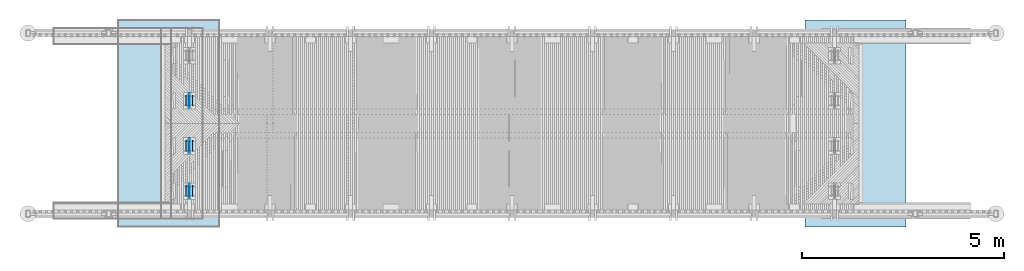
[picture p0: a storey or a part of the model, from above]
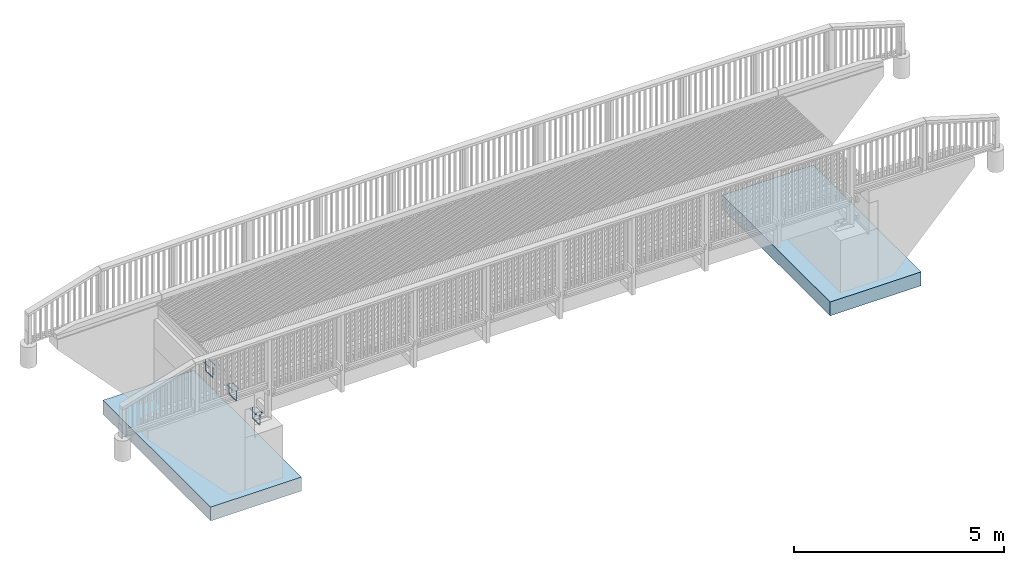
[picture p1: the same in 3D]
Properties of the parts of a building model (IFC2X3), part 1 of 2

# File
Description: ViewDefinition[CoordinationView_V2.0, QuantityTakeOffAddOnView], ExchangeRequirement[Structural, SurfaceGeometry]
File name: HKI_Puusilta_16_sks.ifc
Time: 2018-09-25T11:07:31
Author: SITO\jukka.karenniemi
Organization: Structural Designer
Written by: IFC Database Version:Work
Made in: Tekla Structures 2016i Service Pack 6, IFC Export Version: 4.0.0.0 Sep 13 2017

# IfcSite, Undefined
RefElevation: 0 mm

# IfcBuildingStorey, Undefined
In: Undefined
Elevation: 0 mm

# IfcBeam: 100*60 (32)
In: Undefined
Description: 100*60; Material: TIMBER/Timber_Undefined
Pset_BeamCommon - LoadBearing: yes; Reference: P/0(?)
Tekla Common - Phase: 600; Class: 1
Tekla Quantity - Weight: 1.2 kg; Volume: 0 m3; Gross footprint area: 0 m2; Area per tons: 108.1 m2; Net surface area: 0.1 m2; Height: 100 mm; Width: 55.3 mm; Length: 395 mm
BaseQuantities - Length: 395 mm
Name | Bottom elevation | Top elevation | OuterSurfaceArea (m2) | NetVolume (m3) | NetWeight (kg)
8 x BEAM | +2.484 | +2.584 | 0.12876 | 0.00198487 | 1.19092
8 x BEAM | +2.484 | +2.584 | 0.128766 | 0.00198513 | 1.19108
8 x BEAM | +2.005 | +2.105 | 0.12876 | 0.00198487 | 1.19092
8 x BEAM | +2.005 | +2.105 | 0.128766 | 0.00198513 | 1.19108

# IfcBeam: 150*100 (40)
In: Undefined
Description: 150*100; Material: TIMBER/Timber_Undefined
Tekla Common - Phase: 600; Class: 8004
Tekla Quantity - Volume: 0 m3; Gross footprint area: 0 m2; Height: 150 mm; Width: 100 mm
Pset_BeamCommon - LoadBearing: yes; Reference: TJP/0(?)
Name | Bottom elevation | Top elevation | Weight (kg) | Area per tons (m2) | Net surface area (m2) | Tekla Quantity, Length (mm) | BaseQuantities, Length (mm) | OuterSurfaceArea (m2) | NetVolume (m3) | NetWeight (kg)
4 x TÖRMÄYSJOHDE | +3.069 | +3.209 | 26 | 56.7 | 1.5 | 2885.3 | 2885.28 | 1.47264 | 0.0432791 | 25.9675
2 x TÖRMÄYSJOHDE | +3.145 | +3.249 | 3.6 | 63.9 | 0.2 | 400 | 399.996 | 0.229998 | 0.00599994 | 3.59997
2 x TÖRMÄYSJOHDE | +3.166 | +3.268 | 3.6 | 63.9 | 0.2 | 400 | 399.996 | 0.229998 | 0.00599994 | 3.59997
2 x TÖRMÄYSJOHDE | +3.160 | +3.261 | 3.6 | 63.9 | 0.2 | 400 | 399.996 | 0.229998 | 0.00599994 | 3.59997
2 x TÖRMÄYSJOHDE | +3.126 | +3.229 | 3.6 | 63.9 | 0.2 | 400 | 399.996 | 0.229998 | 0.00599994 | 3.59997
2 x TÖRMÄYSJOHDE | +3.146 | +3.249 | 2.3 | 68.9 | 0.2 | 250 | 250.001 | 0.155 | 0.00375001 | 2.25001
2 x TÖRMÄYSJOHDE | +3.113 | +3.216 | 2.3 | 68.9 | 0.2 | 250 | 250.001 | 0.155 | 0.00375001 | 2.25001
2 x TÖRMÄYSJOHDE | +3.126 | +3.229 | 2.3 | 68.9 | 0.2 | 250 | 250.001 | 0.155 | 0.00375001 | 2.25001
2 x TÖRMÄYSJOHDE | +3.137 | +3.239 | 2.3 | 68.9 | 0.2 | 250 | 250.001 | 0.155 | 0.00375001 | 2.25001
2 x TÖRMÄYSJOHDE | +3.154 | +3.255 | 2.3 | 68.9 | 0.2 | 250 | 250.001 | 0.155 | 0.00375001 | 2.25001
2 x TÖRMÄYSJOHDE | +3.160 | +3.261 | 2.3 | 68.9 | 0.2 | 250 | 250.001 | 0.155 | 0.00375001 | 2.25001
2 x TÖRMÄYSJOHDE | +3.165 | +3.265 | 2.3 | 68.9 | 0.2 | 250 | 250.001 | 0.155 | 0.00375001 | 2.25001
2 x TÖRMÄYSJOHDE | +3.168 | +3.268 | 2.3 | 68.9 | 0.2 | 250 | 250.001 | 0.155 | 0.00375001 | 2.25001
2 x TÖRMÄYSJOHDE | +3.167 | +3.268 | 2.3 | 68.9 | 0.2 | 250 | 250.001 | 0.155 | 0.00375001 | 2.25001
2 x TÖRMÄYSJOHDE | +3.164 | +3.265 | 2.3 | 68.9 | 0.2 | 250 | 250.001 | 0.155 | 0.00375001 | 2.25001
2 x TÖRMÄYSJOHDE | +3.154 | +3.256 | 2.3 | 68.9 | 0.2 | 250 | 250.001 | 0.155 | 0.00375001 | 2.25001
2 x TÖRMÄYSJOHDE | +3.137 | +3.240 | 2.3 | 68.9 | 0.2 | 250 | 250.001 | 0.155 | 0.00375001 | 2.25001
2 x TÖRMÄYSJOHDE | +3.113 | +3.217 | 2.3 | 68.9 | 0.2 | 250 | 250.001 | 0.155 | 0.00375001 | 2.25001
2 x TÖRMÄYSJOHDE | +3.108 | +3.212 | 2.3 | 68.9 | 0.2 | 250 | 250.001 | 0.155 | 0.00375001 | 2.25001

# IfcBeam: 150*150 (18)
In: Undefined
Description: 150*150; Material: TIMBER/Timber_Undefined
Pset_BeamCommon - LoadBearing: yes
Tekla Quantity - Height: 150 mm
Name | Reference | Bottom elevation | Top elevation | Phase | Class | Weight (kg) | Volume (m3) | Gross footprint area (m2) | Area per tons (m2) | Net surface area (m2) | Width (mm) | Tekla Quantity, Length (mm) | BaseQuantities, Length (mm) | OuterSurfaceArea (m2) | NetVolume (m3) | NetWeight (kg)
4 x TÖRMÄYSJOHDE | TJP/0(?) | +3.169 | +3.359 | 600 | 8004 | 36.4 | 0.1 | 0 | 46.9 | 1.7 | 150 | 2885.3 | 2885.28 | 1.70433 | 0.0606248 | 36.3749
6 x BEAM | P/0(?) | +2.584 | +2.734 | 600 | 1 | 12.2 | 0 | 0.1 | 48.1 | 0.6 | 150 | 900 | 900 | 0.585 | 0.02025 | 12.15
2 x BEAM | P/0(?) | +3.034 | +3.151 | 100 | 1 | 34.1 | 0.1 | 0 | 57.4 | 2 | 117.5 | 3930 | 3930 | 1.96088 | 0.0568959 | 34.1375
2 x BEAM | P/0(?) | +2.884 | +3.034 | 100 | 1 | 53.1 | 0.1 | 0.6 | 45.3 | 2.4 | 150 | 3930 | 3930 | 2.403 | 0.088425 | 53.055
2 x BEAM | P/0(?) | +2.734 | +2.884 | 100 | 1 | 53.1 | 0.1 | 0.6 | 45.3 | 2.4 | 150 | 3930 | 3930 | 2.403 | 0.088425 | 53.055
2 x TÖRMÄYSJOHDE | TJP/0(?) | +3.208 | +3.418 | 600 | 8004 | 228.7 | 0.3 | 0.1 | 44.6 | 10.1 | 150 | 16942.7 | 16942.7 | 10.2088 | 0.381144 | 228.686

# IfcBeam: 150*50 (676)
In: Undefined
Description: 150*50; Material: TIMBER/Timber_Undefined
Pset_BeamCommon - LoadBearing: yes; Reference: P/0(?)
Tekla Common - Phase: 400; Class: 1
Tekla Quantity - Volume: 0 m3; Gross footprint area: 0 m2; Height: 150 mm; Width: 50 mm
Name | Bottom elevation | Top elevation | Weight (kg) | Area per tons (m2) | Net surface area (m2) | Tekla Quantity, Length (mm) | BaseQuantities, Length (mm) | OuterSurfaceArea (m2) | NetVolume (m3) | NetWeight (kg)
2 x BEAM | +2.960 | +3.153 | 10.9 | 90.6 | 1 | 2510.6 | 2510.59 | 0.990985 | 0.0182401 | 10.944
2 x BEAM | +2.960 | +3.146 | 8.5 | 91 | 0.8 | 1928.4 | 1928.43 | 0.761386 | 0.013944 | 8.36639
2 x BEAM | +2.959 | +3.145 | 8.5 | 91 | 0.8 | 1928.4 | 1928.43 | 0.761386 | 0.013944 | 8.36639
2 x BEAM | +2.959 | +3.153 | 10.9 | 90.6 | 1 | 2510.6 | 2510.59 | 0.990985 | 0.0182401 | 10.944
2 x BEAM | +2.961 | +3.155 | 10.9 | 90.6 | 1 | 2510.6 | 2510.59 | 0.990985 | 0.0182401 | 10.944
2 x BEAM | +2.961 | +3.147 | 8.5 | 91 | 0.8 | 1928.4 | 1928.43 | 0.761386 | 0.013944 | 8.36639
2 x BEAM | +2.960 | +3.147 | 8.5 | 91 | 0.8 | 1928.4 | 1928.43 | 0.761386 | 0.013944 | 8.36639
2 x BEAM | +2.960 | +3.154 | 10.9 | 90.6 | 1 | 2510.6 | 2510.59 | 0.990985 | 0.0182401 | 10.944
2 x BEAM | +2.962 | +3.156 | 10.9 | 90.6 | 1 | 2510.6 | 2510.59 | 0.990985 | 0.0182401 | 10.944
2 x BEAM | +2.962 | +3.149 | 8.5 | 91 | 0.8 | 1928.4 | 1928.43 | 0.761386 | 0.013944 | 8.36639
2 x BEAM | +2.962 | +3.148 | 8.5 | 91 | 0.8 | 1928.4 | 1928.43 | 0.761386 | 0.013944 | 8.36639
2 x BEAM | +2.962 | +3.155 | 10.9 | 90.6 | 1 | 2510.6 | 2510.59 | 0.990985 | 0.0182401 | 10.944
2 x BEAM | +2.963 | +3.149 | 8.5 | 91 | 0.8 | 1928.4 | 1928.43 | 0.761386 | 0.013944 | 8.36639
2 x BEAM | +2.963 | +3.157 | 10.9 | 90.6 | 1 | 2510.6 | 2510.59 | 0.990985 | 0.0182401 | 10.944
2 x BEAM | +2.965 | +3.159 | 10.9 | 90.6 | 1 | 2510.6 | 2510.59 | 0.990985 | 0.0182401 | 10.944
2 x BEAM | +2.965 | +3.151 | 8.5 | 91 | 0.8 | 1928.4 | 1928.43 | 0.761386 | 0.013944 | 8.36639
2 x BEAM | +2.964 | +3.151 | 8.5 | 91 | 0.8 | 1928.4 | 1928.43 | 0.761386 | 0.013944 | 8.36639
2 x BEAM | +2.964 | +3.158 | 10.9 | 90.6 | 1 | 2510.6 | 2510.59 | 0.990985 | 0.0182401 | 10.944
2 x BEAM | +2.966 | +3.160 | 10.9 | 90.6 | 1 | 2510.6 | 2510.59 | 0.990985 | 0.0182401 | 10.944
2 x BEAM | +2.966 | +3.153 | 8.5 | 91 | 0.8 | 1928.4 | 1928.43 | 0.761386 | 0.013944 | 8.36639
2 x BEAM | +2.968 | +3.161 | 10.9 | 90.6 | 1 | 2510.6 | 2510.59 | 0.990985 | 0.0182401 | 10.944
2 x BEAM | +2.968 | +3.154 | 8.5 | 91 | 0.8 | 1928.4 | 1928.43 | 0.761386 | 0.013944 | 8.36639
2 x BEAM | +2.967 | +3.153 | 8.5 | 91 | 0.8 | 1928.4 | 1928.43 | 0.761386 | 0.013944 | 8.36639
2 x BEAM | +2.967 | +3.161 | 10.9 | 90.6 | 1 | 2510.6 | 2510.59 | 0.990985 | 0.0182401 | 10.944
2 x BEAM | +2.969 | +3.163 | 10.9 | 90.6 | 1 | 2510.6 | 2510.59 | 0.990985 | 0.0182401 | 10.944
2 x BEAM | +2.969 | +3.155 | 8.5 | 91 | 0.8 | 1928.4 | 1928.43 | 0.761386 | 0.013944 | 8.36639
2 x BEAM | +2.968 | +3.155 | 8.5 | 91 | 0.8 | 1928.4 | 1928.43 | 0.761386 | 0.013944 | 8.36639
2 x BEAM | +2.968 | +3.162 | 10.9 | 90.6 | 1 | 2510.6 | 2510.59 | 0.990985 | 0.0182401 | 10.944
2 x BEAM | +2.970 | +3.164 | 10.9 | 90.6 | 1 | 2510.6 | 2510.59 | 0.990985 | 0.0182401 | 10.944
2 x BEAM | +2.970 | +3.157 | 8.5 | 91 | 0.8 | 1928.4 | 1928.43 | 0.761386 | 0.013944 | 8.36639
2 x BEAM | +2.970 | +3.156 | 8.5 | 91 | 0.8 | 1928.4 | 1928.43 | 0.761386 | 0.013944 | 8.36639
2 x BEAM | +2.970 | +3.163 | 10.9 | 90.6 | 1 | 2510.6 | 2510.59 | 0.990985 | 0.0182401 | 10.944
2 x BEAM | +2.971 | +3.165 | 10.9 | 90.6 | 1 | 2510.6 | 2510.59 | 0.990985 | 0.0182401 | 10.944
2 x BEAM | +2.971 | +3.158 | 8.5 | 91 | 0.8 | 1928.4 | 1928.43 | 0.761386 | 0.013944 | 8.36639
2 x BEAM | +2.971 | +3.157 | 8.5 | 91 | 0.8 | 1928.4 | 1928.43 | 0.761386 | 0.013944 | 8.36639
2 x BEAM | +2.971 | +3.164 | 10.9 | 90.6 | 1 | 2510.6 | 2510.59 | 0.990985 | 0.0182401 | 10.944
2 x BEAM | +2.973 | +3.166 | 10.9 | 90.6 | 1 | 2510.6 | 2510.59 | 0.990985 | 0.0182401 | 10.944
2 x BEAM | +2.973 | +3.159 | 8.5 | 91 | 0.8 | 1928.4 | 1928.43 | 0.761386 | 0.013944 | 8.36639
2 x BEAM | +2.972 | +3.158 | 8.5 | 91 | 0.8 | 1928.4 | 1928.43 | 0.761386 | 0.013944 | 8.36639
2 x BEAM | +2.972 | +3.166 | 10.9 | 90.6 | 1 | 2510.6 | 2510.59 | 0.990985 | 0.0182401 | 10.944
2 x BEAM | +2.974 | +3.167 | 10.9 | 90.6 | 1 | 2510.6 | 2510.59 | 0.990985 | 0.0182401 | 10.944
2 x BEAM | +2.974 | +3.160 | 8.5 | 91 | 0.8 | 1928.4 | 1928.43 | 0.761386 | 0.013944 | 8.36639
2 x BEAM | +2.973 | +3.160 | 8.5 | 91 | 0.8 | 1928.4 | 1928.43 | 0.761386 | 0.013944 | 8.36639
2 x BEAM | +2.973 | +3.167 | 10.9 | 90.6 | 1 | 2510.6 | 2510.59 | 0.990985 | 0.0182401 | 10.944
2 x BEAM | +2.975 | +3.169 | 10.9 | 90.6 | 1 | 2510.6 | 2510.59 | 0.990985 | 0.0182401 | 10.944
4 x BEAM | +2.975 | +3.161 | 8.5 | 91 | 0.8 | 1928.4 | 1928.43 | 0.761386 | 0.013944 | 8.36639
2 x BEAM | +2.975 | +3.168 | 10.9 | 90.6 | 1 | 2510.6 | 2510.59 | 0.990985 | 0.0182401 | 10.944
2 x BEAM | +2.976 | +3.170 | 10.9 | 90.6 | 1 | 2510.6 | 2510.59 | 0.990985 | 0.0182401 | 10.944
2 x BEAM | +2.976 | +3.163 | 8.5 | 91 | 0.8 | 1928.4 | 1928.43 | 0.761386 | 0.013944 | 8.36639
2 x BEAM | +2.976 | +3.162 | 8.5 | 91 | 0.8 | 1928.4 | 1928.43 | 0.761386 | 0.013944 | 8.36639
2 x BEAM | +2.976 | +3.169 | 10.9 | 90.6 | 1 | 2510.6 | 2510.59 | 0.990985 | 0.0182401 | 10.944
2 x BEAM | +2.977 | +3.171 | 10.9 | 90.6 | 1 | 2510.6 | 2510.59 | 0.990985 | 0.0182401 | 10.944
2 x BEAM | +2.977 | +3.164 | 8.5 | 91 | 0.8 | 1928.4 | 1928.43 | 0.761386 | 0.013944 | 8.36639
2 x BEAM | +2.977 | +3.163 | 8.5 | 91 | 0.8 | 1928.4 | 1928.43 | 0.761386 | 0.013944 | 8.36639
2 x BEAM | +2.977 | +3.170 | 10.9 | 90.6 | 1 | 2510.6 | 2510.59 | 0.990985 | 0.0182401 | 10.944
2 x BEAM | +2.979 | +3.172 | 10.9 | 90.6 | 1 | 2510.6 | 2510.59 | 0.990985 | 0.0182401 | 10.944
2 x BEAM | +2.979 | +3.165 | 8.5 | 91 | 0.8 | 1928.4 | 1928.43 | 0.761386 | 0.013944 | 8.36639
2 x BEAM | +2.978 | +3.164 | 8.5 | 91 | 0.8 | 1928.4 | 1928.43 | 0.761386 | 0.013944 | 8.36639
2 x BEAM | +2.978 | +3.172 | 10.9 | 90.6 | 1 | 2510.6 | 2510.59 | 0.990985 | 0.0182401 | 10.944
2 x BEAM | +2.980 | +3.173 | 10.9 | 90.6 | 1 | 2510.6 | 2510.59 | 0.990985 | 0.0182401 | 10.944
2 x BEAM | +2.980 | +3.166 | 8.5 | 91 | 0.8 | 1928.4 | 1928.43 | 0.761386 | 0.013944 | 8.36639
2 x BEAM | +2.979 | +3.166 | 8.5 | 91 | 0.8 | 1928.4 | 1928.43 | 0.761386 | 0.013944 | 8.36639
2 x BEAM | +2.979 | +3.173 | 10.9 | 90.6 | 1 | 2510.6 | 2510.59 | 0.990985 | 0.0182401 | 10.944
2 x BEAM | +2.981 | +3.174 | 10.9 | 90.6 | 1 | 2510.6 | 2510.59 | 0.990985 | 0.0182401 | 10.944
2 x BEAM | +2.981 | +3.167 | 8.5 | 91 | 0.8 | 1928.4 | 1928.43 | 0.761386 | 0.013944 | 8.36639
2 x BEAM | +2.980 | +3.167 | 8.5 | 91 | 0.8 | 1928.4 | 1928.43 | 0.761386 | 0.013944 | 8.36639
2 x BEAM | +2.980 | +3.174 | 10.9 | 90.6 | 1 | 2510.6 | 2510.59 | 0.990985 | 0.0182401 | 10.944
2 x BEAM | +2.982 | +3.175 | 10.9 | 90.6 | 1 | 2510.6 | 2510.59 | 0.990985 | 0.0182401 | 10.944
2 x BEAM | +2.982 | +3.168 | 8.5 | 91 | 0.8 | 1928.4 | 1928.43 | 0.761386 | 0.013944 | 8.36639
2 x BEAM | +2.981 | +3.168 | 8.5 | 91 | 0.8 | 1928.4 | 1928.43 | 0.761386 | 0.013944 | 8.36639
2 x BEAM | +2.981 | +3.175 | 10.9 | 90.6 | 1 | 2510.6 | 2510.59 | 0.990985 | 0.0182401 | 10.944
2 x BEAM | +2.983 | +3.177 | 10.9 | 90.6 | 1 | 2510.6 | 2510.59 | 0.990985 | 0.0182401 | 10.944
4 x BEAM | +2.983 | +3.169 | 8.5 | 91 | 0.8 | 1928.4 | 1928.43 | 0.761386 | 0.013944 | 8.36639
2 x BEAM | +2.983 | +3.176 | 10.9 | 90.6 | 1 | 2510.6 | 2510.59 | 0.990985 | 0.0182401 | 10.944
2 x BEAM | +2.984 | +3.178 | 10.9 | 90.6 | 1 | 2510.6 | 2510.59 | 0.990985 | 0.0182401 | 10.944
4 x BEAM | +2.984 | +3.170 | 8.5 | 91 | 0.8 | 1928.4 | 1928.43 | 0.761386 | 0.013944 | 8.36639
2 x BEAM | +2.984 | +3.177 | 10.9 | 90.6 | 1 | 2510.6 | 2510.59 | 0.990985 | 0.0182401 | 10.944
2 x BEAM | +2.985 | +3.179 | 10.9 | 90.6 | 1 | 2510.6 | 2510.59 | 0.990985 | 0.0182401 | 10.944
4 x BEAM | +2.985 | +3.171 | 8.5 | 91 | 0.8 | 1928.4 | 1928.43 | 0.761386 | 0.013944 | 8.36639
2 x BEAM | +2.985 | +3.178 | 10.9 | 90.6 | 1 | 2510.6 | 2510.59 | 0.990985 | 0.0182401 | 10.944
2 x BEAM | +2.986 | +3.180 | 10.9 | 90.6 | 1 | 2510.6 | 2510.59 | 0.990985 | 0.0182401 | 10.944
3 x BEAM | +2.986 | +3.172 | 8.5 | 91 | 0.8 | 1928.4 | 1928.43 | 0.761386 | 0.013944 | 8.36639
2 x BEAM | +2.986 | +3.179 | 10.9 | 90.6 | 1 | 2510.6 | 2510.59 | 0.990985 | 0.0182401 | 10.944
2 x BEAM | +2.987 | +3.173 | 8.5 | 91 | 0.8 | 1928.4 | 1928.43 | 0.761386 | 0.013944 | 8.36639
2 x BEAM | +2.987 | +3.180 | 10.9 | 90.6 | 1 | 2510.6 | 2510.59 | 0.990985 | 0.0182401 | 10.944
2 x BEAM | +2.988 | +3.182 | 10.9 | 90.6 | 1 | 2510.6 | 2510.59 | 0.990985 | 0.0182401 | 10.944
2 x BEAM | +2.988 | +3.175 | 8.5 | 91 | 0.8 | 1928.4 | 1928.43 | 0.761386 | 0.013944 | 8.36639
2 x BEAM | +2.988 | +3.174 | 8.5 | 91 | 0.8 | 1928.4 | 1928.43 | 0.761386 | 0.013944 | 8.36639
2 x BEAM | +2.988 | +3.181 | 10.9 | 90.6 | 1 | 2510.6 | 2510.59 | 0.990985 | 0.0182401 | 10.944
2 x BEAM | +2.989 | +3.183 | 10.9 | 90.6 | 1 | 2510.6 | 2510.59 | 0.990985 | 0.0182401 | 10.944
2 x BEAM | +2.989 | +3.175 | 8.5 | 91 | 0.8 | 1928.4 | 1928.43 | 0.761386 | 0.013944 | 8.36639
2 x BEAM | +2.990 | +3.184 | 10.9 | 90.6 | 1 | 2510.6 | 2510.59 | 0.990985 | 0.0182401 | 10.944
4 x BEAM | +2.990 | +3.176 | 8.5 | 91 | 0.8 | 1928.4 | 1928.43 | 0.761386 | 0.013944 | 8.36639
2 x BEAM | +2.990 | +3.183 | 10.9 | 90.6 | 1 | 2510.6 | 2510.59 | 0.990985 | 0.0182401 | 10.944
2 x BEAM | +2.991 | +3.185 | 10.9 | 90.6 | 1 | 2510.6 | 2510.59 | 0.990985 | 0.0182401 | 10.944
4 x BEAM | +2.991 | +3.177 | 8.5 | 91 | 0.8 | 1928.4 | 1928.43 | 0.761386 | 0.013944 | 8.36639
2 x BEAM | +2.991 | +3.184 | 10.9 | 90.6 | 1 | 2510.6 | 2510.59 | 0.990985 | 0.0182401 | 10.944
2 x BEAM | +2.992 | +3.186 | 10.9 | 90.6 | 1 | 2510.6 | 2510.59 | 0.990985 | 0.0182401 | 10.944
4 x BEAM | +2.992 | +3.178 | 8.5 | 91 | 0.8 | 1928.4 | 1928.43 | 0.761386 | 0.013944 | 8.36639
2 x BEAM | +2.992 | +3.185 | 10.9 | 90.6 | 1 | 2510.6 | 2510.59 | 0.990985 | 0.0182401 | 10.944
4 x BEAM | +2.993 | +3.186 | 10.9 | 90.6 | 1 | 2510.6 | 2510.59 | 0.990985 | 0.0182401 | 10.944
4 x BEAM | +2.993 | +3.179 | 8.5 | 91 | 0.8 | 1928.4 | 1928.43 | 0.761386 | 0.013944 | 8.36639
2 x BEAM | +2.994 | +3.187 | 10.9 | 90.6 | 1 | 2510.6 | 2510.59 | 0.990985 | 0.0182401 | 10.944
2 x BEAM | +2.994 | +3.180 | 8.5 | 91 | 0.8 | 1928.4 | 1928.43 | 0.761386 | 0.013944 | 8.36639
2 x BEAM | +2.993 | +3.180 | 8.5 | 91 | 0.8 | 1928.4 | 1928.43 | 0.761386 | 0.013944 | 8.36639
2 x BEAM | +2.993 | +3.187 | 10.9 | 90.6 | 1 | 2510.6 | 2510.59 | 0.990985 | 0.0182401 | 10.944
2 x BEAM | +2.995 | +3.188 | 10.9 | 90.6 | 1 | 2510.6 | 2510.59 | 0.990985 | 0.0182401 | 10.944
4 x BEAM | +2.995 | +3.181 | 8.5 | 91 | 0.8 | 1928.4 | 1928.43 | 0.761386 | 0.013944 | 8.36639
2 x BEAM | +2.994 | +3.181 | 8.5 | 91 | 0.8 | 1928.4 | 1928.43 | 0.761386 | 0.013944 | 8.36639
2 x BEAM | +2.994 | +3.188 | 10.9 | 90.6 | 1 | 2510.6 | 2510.59 | 0.990985 | 0.0182401 | 10.944
2 x BEAM | +2.996 | +3.189 | 10.9 | 90.6 | 1 | 2510.6 | 2510.59 | 0.990985 | 0.0182401 | 10.944
4 x BEAM | +2.996 | +3.182 | 8.5 | 91 | 0.8 | 1928.4 | 1928.43 | 0.761386 | 0.013944 | 8.36639
2 x BEAM | +2.995 | +3.189 | 10.9 | 90.6 | 1 | 2510.6 | 2510.59 | 0.990985 | 0.0182401 | 10.944
4 x BEAM | +2.997 | +3.190 | 10.9 | 90.6 | 1 | 2510.6 | 2510.59 | 0.990985 | 0.0182401 | 10.944
4 x BEAM | +2.997 | +3.183 | 8.5 | 91 | 0.8 | 1928.4 | 1928.43 | 0.761386 | 0.013944 | 8.36639
2 x BEAM | +2.996 | +3.190 | 10.9 | 90.6 | 1 | 2510.6 | 2510.59 | 0.990985 | 0.0182401 | 10.944
2 x BEAM | +2.997 | +3.191 | 10.9 | 90.6 | 1 | 2510.6 | 2510.59 | 0.990985 | 0.0182401 | 10.944
2 x BEAM | +2.997 | +3.184 | 8.5 | 91 | 0.8 | 1928.4 | 1928.43 | 0.761386 | 0.013944 | 8.36639
2 x BEAM | +2.998 | +3.192 | 10.9 | 90.6 | 1 | 2510.6 | 2510.59 | 0.990985 | 0.0182401 | 10.944
4 x BEAM | +2.998 | +3.184 | 8.5 | 91 | 0.8 | 1928.4 | 1928.43 | 0.761386 | 0.013944 | 8.36639
2 x BEAM | +2.998 | +3.191 | 10.9 | 90.6 | 1 | 2510.6 | 2510.59 | 0.990985 | 0.0182401 | 10.944
4 x BEAM | +2.999 | +3.192 | 10.9 | 90.6 | 1 | 2510.6 | 2510.59 | 0.990985 | 0.0182401 | 10.944
4 x BEAM | +2.999 | +3.185 | 8.5 | 91 | 0.8 | 1928.4 | 1928.43 | 0.761386 | 0.013944 | 8.36639
2 x BEAM | +3.000 | +3.193 | 10.9 | 90.6 | 1 | 2510.6 | 2510.59 | 0.990985 | 0.0182401 | 10.944
4 x BEAM | +3.000 | +3.186 | 8.5 | 91 | 0.8 | 1928.4 | 1928.43 | 0.761386 | 0.013944 | 8.36639
2 x BEAM | +2.999 | +3.186 | 8.5 | 91 | 0.8 | 1928.4 | 1928.43 | 0.761386 | 0.013944 | 8.36639
2 x BEAM | +2.999 | +3.193 | 10.9 | 90.6 | 1 | 2510.6 | 2510.59 | 0.990985 | 0.0182401 | 10.944
4 x BEAM | +3.001 | +3.194 | 10.9 | 90.6 | 1 | 2510.6 | 2510.59 | 0.990985 | 0.0182401 | 10.944
6 x BEAM | +3.001 | +3.187 | 8.5 | 91 | 0.8 | 1928.4 | 1928.43 | 0.761386 | 0.013944 | 8.36639
2 x BEAM | +3.000 | +3.194 | 10.9 | 90.6 | 1 | 2510.6 | 2510.59 | 0.990985 | 0.0182401 | 10.944
2 x BEAM | +3.001 | +3.195 | 10.9 | 90.6 | 1 | 2510.6 | 2510.59 | 0.990985 | 0.0182401 | 10.944
4 x BEAM | +3.002 | +3.195 | 10.9 | 90.6 | 1 | 2510.6 | 2510.59 | 0.990985 | 0.0182401 | 10.944
4 x BEAM | +3.002 | +3.188 | 8.5 | 91 | 0.8 | 1928.4 | 1928.43 | 0.761386 | 0.013944 | 8.36639
4 x BEAM | +3.003 | +3.196 | 10.9 | 90.6 | 1 | 2510.6 | 2510.59 | 0.990985 | 0.0182401 | 10.944
4 x BEAM | +3.003 | +3.189 | 8.5 | 91 | 0.8 | 1928.4 | 1928.43 | 0.761386 | 0.013944 | 8.36639
2 x BEAM | +3.002 | +3.189 | 8.5 | 91 | 0.8 | 1928.4 | 1928.43 | 0.761386 | 0.013944 | 8.36639
2 x BEAM | +3.002 | +3.196 | 10.9 | 90.6 | 1 | 2510.6 | 2510.59 | 0.990985 | 0.0182401 | 10.944
4 x BEAM | +3.004 | +3.197 | 10.9 | 90.6 | 1 | 2510.6 | 2510.59 | 0.990985 | 0.0182401 | 10.944
4 x BEAM | +3.004 | +3.190 | 8.5 | 91 | 0.8 | 1928.4 | 1928.43 | 0.761386 | 0.013944 | 8.36639
4 x BEAM | +3.005 | +3.198 | 10.9 | 90.6 | 1 | 2510.6 | 2510.59 | 0.990985 | 0.0182401 | 10.944
4 x BEAM | +3.005 | +3.191 | 8.5 | 91 | 0.8 | 1928.4 | 1928.43 | 0.761386 | 0.013944 | 8.36639
6 x BEAM | +3.006 | +3.199 | 10.9 | 90.6 | 1 | 2510.6 | 2510.59 | 0.990985 | 0.0182401 | 10.944
6 x BEAM | +3.006 | +3.192 | 8.5 | 91 | 0.8 | 1928.4 | 1928.43 | 0.761386 | 0.013944 | 8.36639
4 x BEAM | +3.007 | +3.200 | 10.9 | 90.6 | 1 | 2510.6 | 2510.59 | 0.990985 | 0.0182401 | 10.944
6 x BEAM | +3.007 | +3.193 | 8.5 | 91 | 0.8 | 1928.4 | 1928.43 | 0.761386 | 0.013944 | 8.36639
2 x BEAM | +3.006 | +3.193 | 8.5 | 91 | 0.8 | 1928.4 | 1928.43 | 0.761386 | 0.013944 | 8.36639
2 x BEAM | +3.006 | +3.200 | 10.9 | 90.6 | 1 | 2510.6 | 2510.59 | 0.990985 | 0.0182401 | 10.944
2 x BEAM | +3.007 | +3.201 | 10.9 | 90.6 | 1 | 2510.6 | 2510.59 | 0.990985 | 0.0182401 | 10.944
4 x BEAM | +3.008 | +3.201 | 10.9 | 90.6 | 1 | 2510.6 | 2510.59 | 0.990985 | 0.0182401 | 10.944
6 x BEAM | +3.008 | +3.194 | 8.5 | 91 | 0.8 | 1928.4 | 1928.43 | 0.761386 | 0.013944 | 8.36639
6 x BEAM | +3.009 | +3.202 | 10.9 | 90.6 | 1 | 2510.6 | 2510.59 | 0.990985 | 0.0182401 | 10.944
8 x BEAM | +3.009 | +3.195 | 8.5 | 91 | 0.8 | 1928.4 | 1928.43 | 0.761386 | 0.013944 | 8.36639
2 x BEAM | +3.008 | +3.202 | 10.9 | 90.6 | 1 | 2510.6 | 2510.59 | 0.990985 | 0.0182401 | 10.944
6 x BEAM | +3.010 | +3.203 | 10.9 | 90.6 | 1 | 2510.6 | 2510.59 | 0.990985 | 0.0182401 | 10.944
8 x BEAM | +3.010 | +3.196 | 8.5 | 91 | 0.8 | 1928.4 | 1928.43 | 0.761386 | 0.013944 | 8.36639
2 x BEAM | +3.009 | +3.203 | 10.9 | 90.6 | 1 | 2510.6 | 2510.59 | 0.990985 | 0.0182401 | 10.944
6 x BEAM | +3.011 | +3.204 | 10.9 | 90.6 | 1 | 2510.6 | 2510.59 | 0.990985 | 0.0182401 | 10.944
8 x BEAM | +3.011 | +3.197 | 8.5 | 91 | 0.8 | 1928.4 | 1928.43 | 0.761386 | 0.013944 | 8.36639
2 x BEAM | +3.010 | +3.204 | 10.9 | 90.6 | 1 | 2510.6 | 2510.59 | 0.990985 | 0.0182401 | 10.944
6 x BEAM | +3.012 | +3.205 | 10.9 | 90.6 | 1 | 2510.6 | 2510.59 | 0.990985 | 0.0182401 | 10.944
8 x BEAM | +3.012 | +3.198 | 8.5 | 91 | 0.8 | 1928.4 | 1928.43 | 0.761386 | 0.013944 | 8.36639
2 x BEAM | +3.011 | +3.205 | 10.9 | 90.6 | 1 | 2510.6 | 2510.59 | 0.990985 | 0.0182401 | 10.944
8 x BEAM | +3.013 | +3.206 | 10.9 | 90.6 | 1 | 2510.6 | 2510.59 | 0.990985 | 0.0182401 | 10.944
10 x BEAM | +3.013 | +3.199 | 8.5 | 91 | 0.8 | 1928.4 | 1928.43 | 0.761386 | 0.013944 | 8.36639
2 x BEAM | +3.012 | +3.206 | 10.9 | 90.6 | 1 | 2510.6 | 2510.59 | 0.990985 | 0.0182401 | 10.944
2 x BEAM | +3.013 | +3.207 | 10.9 | 90.6 | 1 | 2510.6 | 2510.59 | 0.990985 | 0.0182401 | 10.944
10 x BEAM | +3.014 | +3.207 | 10.9 | 90.6 | 1 | 2510.6 | 2510.59 | 0.990985 | 0.0182401 | 10.944
10 x BEAM | +3.014 | +3.200 | 8.5 | 91 | 0.8 | 1928.4 | 1928.43 | 0.761386 | 0.013944 | 8.36639
8 x BEAM | +3.015 | +3.208 | 10.9 | 90.6 | 1 | 2510.6 | 2510.59 | 0.990985 | 0.0182401 | 10.944
10 x BEAM | +3.015 | +3.201 | 8.5 | 91 | 0.8 | 1928.4 | 1928.43 | 0.761386 | 0.013944 | 8.36639
2 x BEAM | +3.015 | +3.209 | 10.9 | 90.6 | 1 | 2510.6 | 2510.59 | 0.990985 | 0.0182401 | 10.944
12 x BEAM | +3.016 | +3.209 | 10.9 | 90.6 | 1 | 2510.6 | 2510.59 | 0.990985 | 0.0182401 | 10.944
14 x BEAM | +3.016 | +3.202 | 8.5 | 91 | 0.8 | 1928.4 | 1928.43 | 0.761386 | 0.013944 | 8.36639
20 x BEAM | +3.017 | +3.210 | 10.9 | 90.6 | 1 | 2510.6 | 2510.59 | 0.990985 | 0.0182401 | 10.944
2 x BEAM | +3.017 | +3.202 | 8.5 | 91 | 0.8 | 1928.4 | 1928.43 | 0.761386 | 0.013944 | 8.36639
2 x BEAM | +3.016 | +3.210 | 10.9 | 90.6 | 1 | 2510.6 | 2510.59 | 0.990985 | 0.0182401 | 10.944
20 x BEAM | +3.017 | +3.203 | 8.5 | 91 | 0.8 | 1928.4 | 1928.43 | 0.761386 | 0.013944 | 8.36639
2 x BEAM | +3.017 | +3.211 | 10.9 | 90.6 | 1 | 2510.6 | 2510.59 | 0.990985 | 0.0182401 | 10.944
32 x BEAM | +3.018 | +3.211 | 10.9 | 90.6 | 1 | 2510.6 | 2510.59 | 0.990985 | 0.0182401 | 10.944
4 x BEAM | +3.018 | +3.203 | 8.5 | 91 | 0.8 | 1928.4 | 1928.43 | 0.761386 | 0.013944 | 8.36639
28 x BEAM | +3.018 | +3.204 | 8.5 | 91 | 0.8 | 1928.4 | 1928.43 | 0.761386 | 0.013944 | 8.36639
2 x BEAM | +2.959 | +3.157 | 12.2 | 90.4 | 1.1 | 2768.6 | 2768.59 | 1.09418 | 0.0201751 | 12.105
2 x BEAM | +2.959 | +3.150 | 9.5 | 90.6 | 0.8 | 2186.4 | 2186.43 | 0.864586 | 0.015879 | 9.52739
2 x BEAM | +2.961 | +3.152 | 9.5 | 90.6 | 0.8 | 2186.4 | 2186.43 | 0.864586 | 0.015879 | 9.52739
2 x BEAM | +2.961 | +3.159 | 12.2 | 90.4 | 1.1 | 2768.6 | 2768.59 | 1.09418 | 0.0201751 | 12.105
2 x BEAM | +2.982 | +3.181 | 12.2 | 90.4 | 1.1 | 2768.6 | 2768.59 | 1.09418 | 0.0201751 | 12.105
2 x BEAM | +2.982 | +3.174 | 9.5 | 90.6 | 0.8 | 2186.4 | 2186.43 | 0.864586 | 0.015879 | 9.52739
2 x BEAM | +2.984 | +3.175 | 9.5 | 90.6 | 0.8 | 2186.4 | 2186.43 | 0.864586 | 0.015879 | 9.52739
2 x BEAM | +2.984 | +3.182 | 12.2 | 90.4 | 1.1 | 2768.6 | 2768.59 | 1.09418 | 0.0201751 | 12.105
2 x BEAM | +2.999 | +3.198 | 12.2 | 90.4 | 1.1 | 2768.6 | 2768.59 | 1.09418 | 0.0201751 | 12.105
2 x BEAM | +2.999 | +3.190 | 9.5 | 90.6 | 0.8 | 2186.4 | 2186.43 | 0.864586 | 0.015879 | 9.52739
2 x BEAM | +3.000 | +3.191 | 9.5 | 90.6 | 0.8 | 2186.4 | 2186.43 | 0.864586 | 0.015879 | 9.52739
BEAM | +3.000 | +3.198 | 12.2 | 90.4 | 1.1 | 2768.6 | 2768.59 | 1.09418 | 0.0201751 | 12.105
2 x BEAM | +3.009 | +3.208 | 12.2 | 90.4 | 1.1 | 2768.6 | 2768.59 | 1.09418 | 0.0201751 | 12.105
2 x BEAM | +3.009 | +3.200 | 9.5 | 90.6 | 0.8 | 2186.4 | 2186.43 | 0.864586 | 0.015879 | 9.52739
2 x BEAM | +3.010 | +3.201 | 9.5 | 90.6 | 0.8 | 2186.4 | 2186.43 | 0.864586 | 0.015879 | 9.52739
2 x BEAM | +3.010 | +3.208 | 12.2 | 90.4 | 1.1 | 2768.6 | 2768.59 | 1.09418 | 0.0201751 | 12.105
2 x BEAM | +3.013 | +3.211 | 12.2 | 90.4 | 1.1 | 2768.6 | 2768.59 | 1.09418 | 0.0201751 | 12.105
2 x BEAM | +3.013 | +3.204 | 9.5 | 90.6 | 0.8 | 2186.4 | 2186.43 | 0.864586 | 0.015879 | 9.52739
BEAM | +3.000 | +3.199 | 12.2 | 90.4 | 1.1 | 2768.6 | 2768.59 | 1.09418 | 0.0201751 | 12.105
BEAM | +2.986 | +3.173 | 8.5 | 91 | 0.8 | 1928.4 | 1928.43 | 0.761386 | 0.013944 | 8.36639

# IfcBeam: 1524*1035 (2)
In: Undefined
Description: 1524*1035; Material: CONCRETE/Concrete_Undefined
Pset_BeamCommon - LoadBearing: yes; Reference: Concrete_LP-1001/0(?)
Tekla Common - Bottom elevation: +0.400; Top elevation: +1.924; Phase: 100; Class: 1007
Tekla Quantity - Weight: 17812.3 kg; Volume: 7.4 m3; Gross footprint area: 1.2 m2; Area per tons: 1.6 m2; Net surface area: 27.8 m2; Height: 1524 mm; Width: 1035 mm; Length: 4730 mm
BaseQuantities - Length: 4730 mm; OuterSurfaceArea: 27.7914 m2; NetVolume: 7.42179 m3; NetWeight: 17812.3 kg

# IfcBeam: 180*100 (18)
In: Undefined
Description: 180*100; Material: TIMBER/Timber_Undefined
Tekla Common - Phase: 600; Class: 8013
Tekla Quantity - Weight: 4 kg; Volume: 0 m3; Gross footprint area: 0 m2; Area per tons: 61 m2; Net surface area: 0.2 m2; Height: 180 mm; Width: 100 mm
Pset_BeamCommon - LoadBearing: yes; Reference: KPP/0(?)
Name | Bottom elevation | Top elevation | Tekla Quantity, Length (mm) | BaseQuantities, Length (mm) | OuterSurfaceArea (m2) | NetVolume (m3) | NetWeight (kg)
2 x KAIDEPYLVÄS | +2.295 | +2.475 | 362.5 | 362.49 | 0.238994 | 0.00652482 | 3.91489
2 x KAIDEPYLVÄS | +2.295 | +2.475 | 363.7 | 363.74 | 0.239694 | 0.00654732 | 3.92839
2 x KAIDEPYLVÄS | +2.318 | +2.498 | 362.5 | 362.49 | 0.238994 | 0.00652482 | 3.91489
2 x KAIDEPYLVÄS | +2.318 | +2.498 | 363.7 | 363.74 | 0.239694 | 0.00654732 | 3.92839
2 x KAIDEPYLVÄS | +2.335 | +2.515 | 362.5 | 362.49 | 0.238994 | 0.00652482 | 3.91489
2 x KAIDEPYLVÄS | +2.335 | +2.515 | 363.7 | 363.74 | 0.239694 | 0.00654732 | 3.92839
2 x KAIDEPYLVÄS | +2.345 | +2.525 | 362.5 | 362.49 | 0.238994 | 0.00652482 | 3.91489
2 x KAIDEPYLVÄS | +2.345 | +2.525 | 363.7 | 363.74 | 0.239694 | 0.00654732 | 3.92839
KAIDEPYLVÄS | +2.348 | +2.528 | 362.5 | 362.49 | 0.238994 | 0.00652482 | 3.91489
KAIDEPYLVÄS | +2.348 | +2.528 | 363.7 | 363.74 | 0.239694 | 0.00654732 | 3.92839

# IfcBeam: 180*70 (6)
In: Undefined
Description: 180*70; Material: TIMBER/Timber_Undefined
Tekla Common - Phase: 600; Class: 8006
Tekla Quantity - Height: 180 mm; Width: 70 mm
Pset_BeamCommon - LoadBearing: yes; Reference: YJP/0(?)
Name | Bottom elevation | Top elevation | Weight (kg) | Volume (m3) | Gross footprint area (m2) | Area per tons (m2) | Net surface area (m2) | Tekla Quantity, Length (mm) | BaseQuantities, Length (mm) | OuterSurfaceArea (m2) | NetVolume (m3) | NetWeight (kg)
4 x YLÄJOHDE | +3.881 | +4.551 | 15.8 | 0 | 0 | 67.8 | 1.1 | 2108 | 2108.03 | 1.06987 | 0.026298 | 15.7788
2 x YLÄJOHDE | +4.480 | +4.633 | 151.8 | 0.3 | 0.1 | 66.3 | 10.1 | 20082.1 | 20082.1 | 10.0657 | 0.25302 | 151.812

# IfcBeam: 195*40 (4)
In: Undefined
Description: 195*40; Material: TIMBER/Timber_Undefined
Pset_BeamCommon - LoadBearing: yes; Reference: P/0(?)
Tekla Common - Bottom elevation: +3.081; Top elevation: +3.149; Phase: 600; Class: 1
Tekla Quantity - Weight: 8.5 kg; Volume: 0 m3; Gross footprint area: 0 m2; Area per tons: 102.3 m2; Net surface area: 0.8 m2; Height: 195 mm; Width: 40 mm; Length: 1820.2 mm
BaseQuantities - Length: 1820.22 mm; OuterSurfaceArea: 0.871104 m2; NetVolume: 0.0141977 m3; NetWeight: 8.51864 kg

# IfcBeam: 195*45 (20)
In: Undefined
Description: 195*45; Material: TIMBER/Timber_Undefined
Pset_BeamCommon - LoadBearing: yes; Reference: P/0(?)
Tekla Common - Phase: 600; Class: 1
Tekla Quantity - Volume: 0 m3; Gross footprint area: 0 m2; Area per tons: 92.9 m2; Net surface area: 0.8 m2; Height: 195 mm; Width: 45 mm
Name | Bottom elevation | Top elevation | Weight (kg) | Tekla Quantity, Length (mm) | BaseQuantities, Length (mm) | OuterSurfaceArea (m2) | NetVolume (m3) | NetWeight (kg)
4 x BEAM | +2.835 | +2.903 | 9.9 | 1880.2 | 1880.22 | 0.920056 | 0.0164989 | 9.89937
4 x BEAM | +2.859 | +2.920 | 9.9 | 1880.2 | 1880.22 | 0.920056 | 0.0164989 | 9.89937
2 x BEAM | +2.875 | +2.930 | 9.9 | 1880.2 | 1880.22 | 0.920056 | 0.0164989 | 9.89937
4 x BEAM | +2.885 | +2.933 | 9.9 | 1880.2 | 1880.22 | 0.920056 | 0.0164989 | 9.89937
2 x BEAM | +2.872 | +2.927 | 9.9 | 1880.2 | 1880.22 | 0.920056 | 0.0164989 | 9.89937
4 x BEAM | +3.107 | +3.180 | 9.7 | 1850.2 | 1850.22 | 0.905656 | 0.0162357 | 9.74142

# IfcBeam: 2800*400 (4)
In: Undefined
Description: 2800*400; Material: CONCRETE/Concrete_Undefined
Tekla Common - Bottom elevation: +0.400; Top elevation: +3.113; Phase: 100; Class: 1013
Tekla Quantity - Weight: 4355.7 kg; Volume: 1.8 m3; Gross footprint area: 0 m2; Area per tons: 3 m2; Net surface area: 13 m2; Height: 2708.8 mm; Width: 400 mm; Length: 2919.2 mm
Pset_BeamCommon - LoadBearing: yes; Reference: Concrete_LP-1001/0(?)
BaseQuantities - Length: 2919.22 mm; OuterSurfaceArea: 13.0098 m2; NetVolume: 1.81489 m3; NetWeight: 4355.74 kg

# IfcBeam: 50*50 (546)
In: Undefined
Description: 50*50; Material: TIMBER/Timber_Undefined
Pset_BeamCommon - LoadBearing: yes; Reference: P/0(?)
Tekla Common - Phase: 400; Class: 1
Tekla Quantity - Volume: 0 m3; Gross footprint area: 0 m2; Width: 50 mm
Name | Bottom elevation | Top elevation | Weight (kg) | Area per tons (m2) | Net surface area (m2) | Height (mm) | Tekla Quantity, Length (mm) | BaseQuantities, Length (mm) | OuterSurfaceArea (m2) | NetVolume (m3) | NetWeight (kg)
2 x BEAM | +3.109 | +3.160 | 0 | 406.5 | 0 | 24.3 | 48.6 | 48.6074 | 0.00683744 | 0.0000280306 | 0.0168184
2 x BEAM | +3.110 | +3.161 | 0.1 | 181.8 | 0 | 50 | 148.6 | 148.584 | 0.0265387 | 0.000243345 | 0.146007
BEAM | +3.149 | +3.200 | 0 | 485.4 | 0 | 19.3 | 39.7 | 39.6953 | 0.00537729 | 0.0000184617 | 0.011077
BEAM | +3.149 | +3.200 | 0 | 485.8 | 0 | 19.3 | 39.7 | 39.6884 | 0.00537407 | 0.0000184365 | 0.0110619
BEAM | +3.147 | +3.201 | 0.1 | 186.6 | 0 | 50 | 139.7 | 139.743 | 0.0247705 | 0.000221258 | 0.132755
BEAM | +3.147 | +3.201 | 0.1 | 186.6 | 0 | 50 | 139.7 | 139.736 | 0.0247626 | 0.000221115 | 0.132669
BEAM | +3.146 | +3.202 | 0.3 | 158.3 | 0 | 50 | 239.8 | 239.789 | 0.0447806 | 0.000471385 | 0.282831
BEAM | +3.146 | +3.202 | 0.3 | 158.3 | 0 | 50 | 239.8 | 239.782 | 0.0447728 | 0.000471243 | 0.282746
BEAM | +3.145 | +3.203 | 0.3 | 151.9 | 0.1 | 50 | 304.5 | 304.465 | 0.0577166 | 0.000633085 | 0.379851
BEAM | +3.145 | +3.203 | 0.3 | 151.9 | 0.1 | 50 | 304.5 | 304.458 | 0.0577088 | 0.000632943 | 0.379766
BEAM | +3.144 | +3.204 | 0.5 | 146.7 | 0.1 | 50 | 404.5 | 404.51 | 0.0777266 | 0.000883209 | 0.529926
BEAM | +3.144 | +3.204 | 0.5 | 146.7 | 0.1 | 50 | 404.5 | 404.504 | 0.0777187 | 0.000883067 | 0.52984
BEAM | +3.142 | +3.205 | 0.7 | 143.7 | 0.1 | 50 | 504.6 | 504.555 | 0.0977363 | 0.00113333 | 0.679999
BEAM | +3.142 | +3.205 | 0.7 | 143.7 | 0.1 | 50 | 504.5 | 504.548 | 0.0977285 | 0.00113319 | 0.679914
BEAM | +3.141 | +3.206 | 0.7 | 141.9 | 0.1 | 50 | 604.6 | 604.599 | 0.117746 | 0.00138345 | 0.830072
BEAM | +3.141 | +3.206 | 0.7 | 141.9 | 0.1 | 50 | 604.6 | 604.592 | 0.117738 | 0.00138331 | 0.829986
BEAM | +3.139 | +3.207 | 0.9 | 140.5 | 0.1 | 50 | 704.6 | 704.643 | 0.137756 | 0.00163357 | 0.980143
BEAM | +3.139 | +3.207 | 0.9 | 140.5 | 0.1 | 50 | 704.6 | 704.636 | 0.137748 | 0.00163343 | 0.980058
BEAM | +3.138 | +3.208 | 1.1 | 139.6 | 0.2 | 50 | 804.7 | 804.685 | 0.157765 | 0.00188369 | 1.13021
BEAM | +3.138 | +3.208 | 1.1 | 139.6 | 0.2 | 50 | 804.7 | 804.679 | 0.157757 | 0.00188355 | 1.13013
BEAM | +3.136 | +3.209 | 1.2 | 138.9 | 0.2 | 50 | 904.7 | 904.727 | 0.177774 | 0.00213381 | 1.28028
BEAM | +3.136 | +3.209 | 1.2 | 138.9 | 0.2 | 50 | 904.7 | 904.721 | 0.177766 | 0.00213366 | 1.2802
BEAM | +3.135 | +3.210 | 1.5 | 138.3 | 0.2 | 50 | 1004.8 | 1004.77 | 0.197783 | 0.00238392 | 1.43035
BEAM | +3.135 | +3.210 | 1.5 | 138.3 | 0.2 | 50 | 1004.8 | 1004.76 | 0.197775 | 0.00238378 | 1.43027
BEAM | +3.133 | +3.210 | 1.6 | 137.8 | 0.2 | 50 | 1104.8 | 1104.81 | 0.217792 | 0.00263403 | 1.58042
BEAM | +3.133 | +3.210 | 1.6 | 137.8 | 0.2 | 50 | 1104.8 | 1104.8 | 0.217784 | 0.00263389 | 1.58033
BEAM | +3.132 | +3.211 | 1.8 | 137.4 | 0.2 | 50 | 1204.8 | 1204.85 | 0.237801 | 0.00288414 | 1.73049
BEAM | +3.132 | +3.211 | 1.8 | 137.4 | 0.2 | 50 | 1204.8 | 1204.84 | 0.237793 | 0.002884 | 1.7304
BEAM | +3.130 | +3.212 | 2 | 137.1 | 0.3 | 50 | 1304.9 | 1304.89 | 0.25781 | 0.00313425 | 1.88055
BEAM | +3.130 | +3.212 | 2 | 137.1 | 0.3 | 50 | 1304.9 | 1304.88 | 0.257802 | 0.00313411 | 1.88047
BEAM | +3.129 | +3.213 | 2 | 136.8 | 0.3 | 50 | 1404.9 | 1404.93 | 0.277818 | 0.00338436 | 2.03062
BEAM | +3.129 | +3.213 | 2 | 136.8 | 0.3 | 50 | 1404.9 | 1404.92 | 0.277811 | 0.00338422 | 2.03053
BEAM | +3.127 | +3.214 | 2.2 | 136.6 | 0.3 | 50 | 1505 | 1504.97 | 0.297827 | 0.00363447 | 2.18068
BEAM | +3.127 | +3.214 | 2.2 | 136.6 | 0.3 | 50 | 1505 | 1504.96 | 0.297819 | 0.00363432 | 2.18059
BEAM | +3.126 | +3.215 | 2.3 | 136.4 | 0.3 | 50 | 1605 | 1605 | 0.317835 | 0.00388457 | 2.33074
BEAM | +3.126 | +3.215 | 2.3 | 136.4 | 0.3 | 50 | 1605 | 1605 | 0.317827 | 0.00388443 | 2.33066
BEAM | +3.125 | +3.216 | 2.5 | 136.2 | 0.3 | 50 | 1705 | 1705.04 | 0.337844 | 0.00413467 | 2.4808
BEAM | +3.125 | +3.216 | 2.5 | 136.2 | 0.3 | 50 | 1705 | 1705.03 | 0.337836 | 0.00413453 | 2.48072
BEAM | +3.123 | +3.217 | 2.6 | 136 | 0.3 | 50 | 1805.1 | 1805.08 | 0.357852 | 0.00438478 | 2.63087
BEAM | +3.123 | +3.217 | 2.6 | 136 | 0.3 | 50 | 1805.1 | 1805.07 | 0.357844 | 0.00438463 | 2.63078
BEAM | +3.122 | +3.218 | 2.8 | 136 | 0.3 | 50 | 1905.1 | 1905.11 | 0.37786 | 0.00463488 | 2.78093
BEAM | +3.122 | +3.218 | 2.8 | 136 | 0.3 | 50 | 1905.1 | 1905.11 | 0.377852 | 0.00463473 | 2.78084
BEAM | +3.120 | +3.218 | 2.9 | 135.7 | 0.3 | 50 | 2005.1 | 2005.15 | 0.397867 | 0.00488497 | 2.93098
BEAM | +3.120 | +3.218 | 2.9 | 135.7 | 0.3 | 50 | 2005.1 | 2005.14 | 0.39786 | 0.00488483 | 2.9309
BEAM | +3.119 | +3.219 | 3.1 | 135.6 | 0.3 | 50 | 2105.2 | 2105.18 | 0.417875 | 0.00513507 | 3.08104
BEAM | +3.119 | +3.219 | 3.1 | 135.6 | 0.3 | 50 | 2105.2 | 2105.18 | 0.417867 | 0.00513493 | 3.08096
BEAM | +3.118 | +3.220 | 3.2 | 135.6 | 0.3 | 50 | 2205.2 | 2205.22 | 0.437883 | 0.00538517 | 3.2311
BEAM | +3.118 | +3.220 | 3.2 | 135.6 | 0.3 | 50 | 2205.2 | 2205.21 | 0.437875 | 0.00538502 | 3.23101
BEAM | +3.116 | +3.221 | 3.4 | 135.4 | 0.5 | 50 | 2305.2 | 2305.25 | 0.45789 | 0.00563526 | 3.38116
BEAM | +3.116 | +3.221 | 3.4 | 135.4 | 0.5 | 50 | 2305.2 | 2305.24 | 0.457882 | 0.00563512 | 3.38107
BEAM | +3.115 | +3.222 | 3.4 | 135.4 | 0.5 | 50 | 2405.3 | 2405.28 | 0.477898 | 0.00588535 | 3.53121
BEAM | +3.115 | +3.222 | 3.4 | 135.4 | 0.5 | 50 | 2405.3 | 2405.27 | 0.47789 | 0.00588521 | 3.53112
BEAM | +3.114 | +3.222 | 3.7 | 135.4 | 0.5 | 50 | 2505.3 | 2505.31 | 0.497905 | 0.00613544 | 3.68126
BEAM | +3.114 | +3.222 | 3.7 | 135.4 | 0.5 | 50 | 2505.3 | 2505.31 | 0.497897 | 0.0061353 | 3.68118
BEAM | +3.112 | +3.223 | 3.8 | 135.2 | 0.5 | 50 | 2605.3 | 2605.34 | 0.517912 | 0.00638553 | 3.83132
BEAM | +3.112 | +3.223 | 3.8 | 135.2 | 0.5 | 50 | 2605.3 | 2605.34 | 0.517904 | 0.00638539 | 3.83123
BEAM | +3.111 | +3.224 | 4 | 135.1 | 0.5 | 50 | 2705.4 | 2705.38 | 0.537919 | 0.00663562 | 3.98137
BEAM | +3.111 | +3.224 | 4 | 135.1 | 0.5 | 50 | 2705.4 | 2705.37 | 0.537911 | 0.00663548 | 3.98129
BEAM | +3.110 | +3.225 | 4.1 | 135.1 | 0.6 | 50 | 2805.4 | 2805.41 | 0.557926 | 0.0068857 | 4.13142
BEAM | +3.110 | +3.225 | 4.1 | 135.1 | 0.6 | 50 | 2805.4 | 2805.4 | 0.557918 | 0.00688556 | 4.13134
BEAM | +3.109 | +3.226 | 4.1 | 135.1 | 0.6 | 50 | 2880.8 | 2880.77 | 0.572949 | 0.0070735 | 4.2441
BEAM | +3.109 | +3.226 | 4.1 | 135.1 | 0.6 | 50 | 2880.8 | 2880.76 | 0.572941 | 0.00707335 | 4.24401
BEAM | +3.110 | +3.226 | 4.1 | 135.1 | 0.6 | 50 | 2880.8 | 2880.77 | 0.572949 | 0.0070735 | 4.2441
BEAM | +3.110 | +3.226 | 4.1 | 135.1 | 0.6 | 50 | 2880.8 | 2880.76 | 0.572941 | 0.00707335 | 4.24401
BEAM | +3.111 | +3.227 | 4.1 | 135.1 | 0.6 | 50 | 2880.8 | 2880.77 | 0.572949 | 0.0070735 | 4.2441
BEAM | +3.111 | +3.227 | 4.1 | 135.1 | 0.6 | 50 | 2880.8 | 2880.76 | 0.572941 | 0.00707335 | 4.24401
BEAM | +3.112 | +3.228 | 4.1 | 135.1 | 0.6 | 50 | 2880.8 | 2880.77 | 0.572949 | 0.0070735 | 4.2441
BEAM | +3.112 | +3.228 | 4.1 | 135.1 | 0.6 | 50 | 2880.8 | 2880.76 | 0.572941 | 0.00707335 | 4.24401
BEAM | +3.113 | +3.229 | 4.1 | 135.1 | 0.6 | 50 | 2880.8 | 2880.77 | 0.572949 | 0.0070735 | 4.2441
BEAM | +3.113 | +3.229 | 4.1 | 135.1 | 0.6 | 50 | 2880.8 | 2880.76 | 0.572941 | 0.00707335 | 4.24401
BEAM | +3.114 | +3.229 | 4.1 | 135.1 | 0.6 | 50 | 2880.8 | 2880.77 | 0.572949 | 0.0070735 | 4.2441
BEAM | +3.114 | +3.229 | 4.1 | 135.1 | 0.6 | 50 | 2880.8 | 2880.76 | 0.572941 | 0.00707335 | 4.24401
BEAM | +3.115 | +3.230 | 4.1 | 135.1 | 0.6 | 50 | 2880.8 | 2880.77 | 0.572949 | 0.0070735 | 4.2441
BEAM | +3.115 | +3.230 | 4.1 | 135.1 | 0.6 | 50 | 2880.8 | 2880.76 | 0.572941 | 0.00707335 | 4.24401
BEAM | +3.116 | +3.231 | 4.1 | 135.1 | 0.6 | 50 | 2880.8 | 2880.77 | 0.572949 | 0.0070735 | 4.2441
BEAM | +3.116 | +3.231 | 4.1 | 135.1 | 0.6 | 50 | 2880.8 | 2880.76 | 0.572941 | 0.00707335 | 4.24401
BEAM | +3.117 | +3.231 | 4.1 | 135.1 | 0.6 | 50 | 2880.8 | 2880.77 | 0.572949 | 0.0070735 | 4.2441
BEAM | +3.117 | +3.231 | 4.1 | 135.1 | 0.6 | 50 | 2880.8 | 2880.76 | 0.572941 | 0.00707335 | 4.24401
BEAM | +3.118 | +3.232 | 4.1 | 135.1 | 0.6 | 50 | 2880.8 | 2880.77 | 0.572949 | 0.0070735 | 4.2441
BEAM | +3.118 | +3.232 | 4.1 | 135.1 | 0.6 | 50 | 2880.8 | 2880.76 | 0.572941 | 0.00707335 | 4.24401
BEAM | +3.119 | +3.233 | 4.1 | 135.1 | 0.6 | 50 | 2880.8 | 2880.77 | 0.572949 | 0.0070735 | 4.2441
BEAM | +3.119 | +3.233 | 4.1 | 135.1 | 0.6 | 50 | 2880.8 | 2880.76 | 0.572941 | 0.00707335 | 4.24401
BEAM | +3.120 | +3.234 | 4.1 | 135.1 | 0.6 | 50 | 2880.8 | 2880.77 | 0.572949 | 0.0070735 | 4.2441
BEAM | +3.120 | +3.234 | 4.1 | 135.1 | 0.6 | 50 | 2880.8 | 2880.76 | 0.572941 | 0.00707335 | 4.24401
BEAM | +3.121 | +3.234 | 4.1 | 135.1 | 0.6 | 50 | 2880.8 | 2880.77 | 0.572949 | 0.0070735 | 4.2441
BEAM | +3.121 | +3.234 | 4.1 | 135.1 | 0.6 | 50 | 2880.8 | 2880.76 | 0.572941 | 0.00707335 | 4.24401
BEAM | +3.122 | +3.235 | 4.1 | 135.1 | 0.6 | 50 | 2880.8 | 2880.77 | 0.572949 | 0.0070735 | 4.2441
BEAM | +3.122 | +3.235 | 4.1 | 135.1 | 0.6 | 50 | 2880.8 | 2880.76 | 0.572941 | 0.00707335 | 4.24401
2 x BEAM | +3.123 | +3.236 | 4.1 | 135.1 | 0.6 | 50 | 2880.8 | 2880.77 | 0.572949 | 0.0070735 | 4.2441
2 x BEAM | +3.123 | +3.236 | 4.1 | 135.1 | 0.6 | 50 | 2880.8 | 2880.76 | 0.572941 | 0.00707335 | 4.24401
2 x BEAM | +3.111 | +3.163 | 0.3 | 157.2 | 0 | 50 | 248.6 | 248.561 | 0.046535 | 0.000493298 | 0.295979
2 x BEAM | +3.112 | +3.164 | 0.3 | 149.2 | 0.1 | 50 | 348.5 | 348.539 | 0.0665313 | 0.000743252 | 0.445951
2 x BEAM | +3.113 | +3.165 | 0.7 | 145.2 | 0.1 | 50 | 448.5 | 448.517 | 0.0865276 | 0.000993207 | 0.595924
2 x BEAM | +3.114 | +3.167 | 0.7 | 142.8 | 0.1 | 50 | 548.5 | 548.495 | 0.106524 | 0.00124316 | 0.745897
2 x BEAM | +3.115 | +3.168 | 0.9 | 141.2 | 0.1 | 50 | 648.5 | 648.473 | 0.126521 | 0.00149312 | 0.89587
2 x BEAM | +3.116 | +3.169 | 0.9 | 140.1 | 0.1 | 50 | 748.5 | 748.452 | 0.146517 | 0.00174307 | 1.04584
2 x BEAM | +3.117 | +3.171 | 1.2 | 139.2 | 0.2 | 50 | 848.4 | 848.43 | 0.166514 | 0.00199303 | 1.19582
2 x BEAM | +3.118 | +3.172 | 1.2 | 138.6 | 0.2 | 50 | 948.4 | 948.41 | 0.18651 | 0.00224299 | 1.34579
2 x BEAM | +3.119 | +3.174 | 1.5 | 138.1 | 0.2 | 50 | 1048.4 | 1048.39 | 0.206507 | 0.00249295 | 1.49577
2 x BEAM | +3.120 | +3.175 | 1.6 | 137.6 | 0.2 | 50 | 1148.4 | 1148.37 | 0.226504 | 0.00274291 | 1.64574
2 x BEAM | +3.120 | +3.176 | 1.8 | 137.4 | 0.2 | 50 | 1248.3 | 1248.35 | 0.246501 | 0.00299287 | 1.79572
2 x BEAM | +3.121 | +3.178 | 2 | 137.1 | 0.3 | 50 | 1348.3 | 1348.33 | 0.266497 | 0.00324283 | 1.9457
2 x BEAM | +3.122 | +3.179 | 2.1 | 136.8 | 0.3 | 50 | 1448.3 | 1448.31 | 0.286494 | 0.00349279 | 2.09567
2 x BEAM | +3.123 | +3.181 | 2.2 | 136.4 | 0.3 | 50 | 1548.3 | 1548.29 | 0.306491 | 0.00374275 | 2.24565
2 x BEAM | +3.124 | +3.182 | 2.5 | 136.2 | 0.3 | 50 | 1648.3 | 1648.27 | 0.326488 | 0.00399272 | 2.39563
2 x BEAM | +3.125 | +3.183 | 2.5 | 136 | 0.3 | 50 | 1748.3 | 1748.25 | 0.346485 | 0.00424268 | 2.54561
2 x BEAM | +3.126 | +3.185 | 2.7 | 136 | 0.3 | 50 | 1848.2 | 1848.24 | 0.366483 | 0.00449264 | 2.69559
2 x BEAM | +3.127 | +3.186 | 2.8 | 135.7 | 0.3 | 50 | 1948.2 | 1948.22 | 0.38648 | 0.00474261 | 2.84557
2 x BEAM | +3.127 | +3.188 | 2.9 | 135.7 | 0.3 | 50 | 2048.2 | 2048.2 | 0.406477 | 0.00499258 | 2.99555
2 x BEAM | +3.128 | +3.189 | 3.1 | 135.6 | 0.3 | 50 | 2148.2 | 2148.18 | 0.426475 | 0.00524254 | 3.14553
2 x BEAM | +3.129 | +3.191 | 3.3 | 135.4 | 0.3 | 50 | 2248.2 | 2248.17 | 0.446472 | 0.00549251 | 3.29551
2 x BEAM | +3.130 | +3.192 | 3.4 | 135.4 | 0.5 | 50 | 2348.1 | 2348.15 | 0.46647 | 0.00574248 | 3.44549
2 x BEAM | +3.131 | +3.194 | 3.6 | 135.2 | 0.5 | 50 | 2448.1 | 2448.13 | 0.486467 | 0.00599245 | 3.59547
2 x BEAM | +3.132 | +3.195 | 3.7 | 135.2 | 0.5 | 50 | 2548.1 | 2548.12 | 0.506465 | 0.00624242 | 3.74545
2 x BEAM | +3.132 | +3.197 | 4 | 135.1 | 0.5 | 50 | 2648.1 | 2648.1 | 0.526462 | 0.00649239 | 3.89543
2 x BEAM | +3.133 | +3.198 | 4 | 135.1 | 0.5 | 50 | 2748.1 | 2748.09 | 0.54646 | 0.00674236 | 4.04542
BEAM | +3.134 | +3.200 | 4.1 | 134.8 | 0.6 | 50 | 2839 | 2839.02 | 0.565431 | 0.00698851 | 4.19311
BEAM | +3.134 | +3.200 | 4.1 | 134.8 | 0.6 | 50 | 2839 | 2838.97 | 0.565424 | 0.00698847 | 4.19308
BEAM | +3.135 | +3.201 | 4.1 | 135.1 | 0.6 | 50 | 2880.8 | 2880.77 | 0.572949 | 0.0070735 | 4.2441
BEAM | +3.135 | +3.201 | 4.1 | 135.1 | 0.6 | 50 | 2880.8 | 2880.76 | 0.572941 | 0.00707335 | 4.24401
BEAM | +3.136 | +3.202 | 4.1 | 135.1 | 0.6 | 50 | 2880.8 | 2880.77 | 0.572949 | 0.0070735 | 4.2441
BEAM | +3.136 | +3.202 | 4.1 | 135.1 | 0.6 | 50 | 2880.8 | 2880.76 | 0.572941 | 0.00707335 | 4.24401
BEAM | +3.136 | +3.203 | 4.1 | 135.1 | 0.6 | 50 | 2880.8 | 2880.77 | 0.572949 | 0.0070735 | 4.2441
BEAM | +3.136 | +3.203 | 4.1 | 135.1 | 0.6 | 50 | 2880.8 | 2880.76 | 0.572941 | 0.00707335 | 4.24401
BEAM | +3.137 | +3.204 | 4.1 | 135.1 | 0.6 | 50 | 2880.8 | 2880.77 | 0.572949 | 0.0070735 | 4.2441
BEAM | +3.137 | +3.204 | 4.1 | 135.1 | 0.6 | 50 | 2880.8 | 2880.76 | 0.572941 | 0.00707335 | 4.24401
BEAM | +3.138 | +3.205 | 4.1 | 135.1 | 0.6 | 50 | 2880.8 | 2880.77 | 0.572949 | 0.0070735 | 4.2441
BEAM | +3.138 | +3.205 | 4.1 | 135.1 | 0.6 | 50 | 2880.8 | 2880.76 | 0.572941 | 0.00707335 | 4.24401
BEAM | +3.139 | +3.206 | 4.1 | 135.1 | 0.6 | 50 | 2880.8 | 2880.77 | 0.572949 | 0.0070735 | 4.2441
BEAM | +3.139 | +3.206 | 4.1 | 135.1 | 0.6 | 50 | 2880.8 | 2880.76 | 0.572941 | 0.00707335 | 4.24401
BEAM | +3.139 | +3.207 | 4.1 | 135.1 | 0.6 | 50 | 2880.8 | 2880.77 | 0.572949 | 0.0070735 | 4.2441
BEAM | +3.139 | +3.207 | 4.1 | 135.1 | 0.6 | 50 | 2880.8 | 2880.76 | 0.572941 | 0.00707335 | 4.24401
BEAM | +3.140 | +3.208 | 4.1 | 135.1 | 0.6 | 50 | 2880.8 | 2880.77 | 0.572949 | 0.0070735 | 4.2441
BEAM | +3.140 | +3.208 | 4.1 | 135.1 | 0.6 | 50 | 2880.8 | 2880.76 | 0.572941 | 0.00707335 | 4.24401
2 x BEAM | +3.141 | +3.209 | 4.1 | 135.1 | 0.6 | 50 | 2880.8 | 2880.77 | 0.572949 | 0.0070735 | 4.2441
2 x BEAM | +3.141 | +3.209 | 4.1 | 135.1 | 0.6 | 50 | 2880.8 | 2880.76 | 0.572941 | 0.00707335 | 4.24401
BEAM | +3.142 | +3.210 | 4.1 | 135.1 | 0.6 | 50 | 2880.8 | 2880.77 | 0.572949 | 0.0070735 | 4.2441
BEAM | +3.142 | +3.210 | 4.1 | 135.1 | 0.6 | 50 | 2880.8 | 2880.76 | 0.572941 | 0.00707335 | 4.24401
BEAM | +3.143 | +3.211 | 4.1 | 135.1 | 0.6 | 50 | 2880.8 | 2880.77 | 0.572949 | 0.0070735 | 4.2441
BEAM | +3.143 | +3.211 | 4.1 | 135.1 | 0.6 | 50 | 2880.8 | 2880.76 | 0.572941 | 0.00707335 | 4.24401
BEAM | +3.143 | +3.212 | 4.1 | 135.1 | 0.6 | 50 | 2880.8 | 2880.77 | 0.572949 | 0.0070735 | 4.2441
BEAM | +3.143 | +3.212 | 4.1 | 135.1 | 0.6 | 50 | 2880.8 | 2880.76 | 0.572941 | 0.00707335 | 4.24401
BEAM | +3.144 | +3.213 | 4.1 | 135.1 | 0.6 | 50 | 2880.8 | 2880.77 | 0.572949 | 0.0070735 | 4.2441
BEAM | +3.144 | +3.213 | 4.1 | 135.1 | 0.6 | 50 | 2880.8 | 2880.76 | 0.572941 | 0.00707335 | 4.24401
BEAM | +3.145 | +3.214 | 4.1 | 135.1 | 0.6 | 50 | 2880.8 | 2880.77 | 0.572949 | 0.0070735 | 4.2441
BEAM | +3.145 | +3.214 | 4.1 | 135.1 | 0.6 | 50 | 2880.8 | 2880.76 | 0.572941 | 0.00707335 | 4.24401
BEAM | +3.145 | +3.215 | 4.1 | 135.1 | 0.6 | 50 | 2880.8 | 2880.77 | 0.572949 | 0.0070735 | 4.2441
BEAM | +3.145 | +3.215 | 4.1 | 135.1 | 0.6 | 50 | 2880.8 | 2880.76 | 0.572941 | 0.00707335 | 4.24401
BEAM | +3.146 | +3.216 | 4.1 | 135.1 | 0.6 | 50 | 2880.8 | 2880.77 | 0.572949 | 0.0070735 | 4.2441
BEAM | +3.146 | +3.216 | 4.1 | 135.1 | 0.6 | 50 | 2880.8 | 2880.76 | 0.572941 | 0.00707335 | 4.24401
2 x BEAM | +3.147 | +3.217 | 4.1 | 135.1 | 0.6 | 50 | 2880.8 | 2880.77 | 0.572949 | 0.0070735 | 4.2441
2 x BEAM | +3.147 | +3.217 | 4.1 | 135.1 | 0.6 | 50 | 2880.8 | 2880.76 | 0.572941 | 0.00707335 | 4.24401
BEAM | +3.148 | +3.218 | 4.1 | 135.1 | 0.6 | 50 | 2880.8 | 2880.77 | 0.572949 | 0.0070735 | 4.2441
BEAM | +3.148 | +3.218 | 4.1 | 135.1 | 0.6 | 50 | 2880.8 | 2880.76 | 0.572941 | 0.00707335 | 4.24401
BEAM | +3.149 | +3.219 | 4.1 | 135.1 | 0.6 | 50 | 2880.8 | 2880.77 | 0.572949 | 0.0070735 | 4.2441
BEAM | +3.149 | +3.219 | 4.1 | 135.1 | 0.6 | 50 | 2880.8 | 2880.76 | 0.572941 | 0.00707335 | 4.24401
BEAM | +3.149 | +3.220 | 4.1 | 135.1 | 0.6 | 50 | 2880.8 | 2880.77 | 0.572949 | 0.0070735 | 4.2441
BEAM | +3.149 | +3.220 | 4.1 | 135.1 | 0.6 | 50 | 2880.8 | 2880.76 | 0.572941 | 0.00707335 | 4.24401
BEAM | +3.150 | +3.221 | 4.1 | 135.1 | 0.6 | 50 | 2880.8 | 2880.77 | 0.572949 | 0.0070735 | 4.2441
BEAM | +3.150 | +3.221 | 4.1 | 135.1 | 0.6 | 50 | 2880.8 | 2880.76 | 0.572941 | 0.00707335 | 4.24401
BEAM | +3.150 | +3.222 | 4.1 | 135.1 | 0.6 | 50 | 2880.8 | 2880.77 | 0.572949 | 0.0070735 | 4.2441
BEAM | +3.150 | +3.222 | 4.1 | 135.1 | 0.6 | 50 | 2880.8 | 2880.76 | 0.572941 | 0.00707335 | 4.24401
BEAM | +3.151 | +3.222 | 4.1 | 135.1 | 0.6 | 50 | 2880.8 | 2880.77 | 0.572949 | 0.0070735 | 4.2441
BEAM | +3.151 | +3.222 | 4.1 | 135.1 | 0.6 | 50 | 2880.8 | 2880.76 | 0.572941 | 0.00707335 | 4.24401
BEAM | +3.152 | +3.223 | 4.1 | 135.1 | 0.6 | 50 | 2880.8 | 2880.77 | 0.572949 | 0.0070735 | 4.2441
BEAM | +3.152 | +3.223 | 4.1 | 135.1 | 0.6 | 50 | 2880.8 | 2880.76 | 0.572941 | 0.00707335 | 4.24401
BEAM | +3.152 | +3.224 | 4.1 | 135.1 | 0.6 | 50 | 2880.8 | 2880.77 | 0.572949 | 0.0070735 | 4.2441
BEAM | +3.152 | +3.224 | 4.1 | 135.1 | 0.6 | 50 | 2880.8 | 2880.76 | 0.572941 | 0.00707335 | 4.24401
BEAM | +3.153 | +3.225 | 4.1 | 135.1 | 0.6 | 50 | 2880.8 | 2880.77 | 0.572949 | 0.0070735 | 4.2441
BEAM | +3.153 | +3.225 | 4.1 | 135.1 | 0.6 | 50 | 2880.8 | 2880.76 | 0.572941 | 0.00707335 | 4.24401
BEAM | +3.153 | +3.226 | 4.1 | 135.1 | 0.6 | 50 | 2880.8 | 2880.77 | 0.572949 | 0.0070735 | 4.2441
BEAM | +3.153 | +3.226 | 4.1 | 135.1 | 0.6 | 50 | 2880.8 | 2880.76 | 0.572941 | 0.00707335 | 4.24401
BEAM | +3.154 | +3.226 | 4.1 | 135.1 | 0.6 | 50 | 2880.8 | 2880.77 | 0.572949 | 0.0070735 | 4.2441
BEAM | +3.154 | +3.226 | 4.1 | 135.1 | 0.6 | 50 | 2880.8 | 2880.76 | 0.572941 | 0.00707335 | 4.24401
BEAM | +3.154 | +3.227 | 4.1 | 135.1 | 0.6 | 50 | 2880.8 | 2880.77 | 0.572949 | 0.0070735 | 4.2441
BEAM | +3.154 | +3.227 | 4.1 | 135.1 | 0.6 | 50 | 2880.8 | 2880.76 | 0.572941 | 0.00707335 | 4.24401
BEAM | +3.155 | +3.228 | 4.1 | 135.1 | 0.6 | 50 | 2880.8 | 2880.77 | 0.572949 | 0.0070735 | 4.2441
BEAM | +3.155 | +3.228 | 4.1 | 135.1 | 0.6 | 50 | 2880.8 | 2880.76 | 0.572941 | 0.00707335 | 4.24401
BEAM | +3.155 | +3.229 | 4.1 | 135.1 | 0.6 | 50 | 2880.8 | 2880.77 | 0.572949 | 0.0070735 | 4.2441
BEAM | +3.155 | +3.229 | 4.1 | 135.1 | 0.6 | 50 | 2880.8 | 2880.76 | 0.572941 | 0.00707335 | 4.24401
BEAM | +3.156 | +3.229 | 4.1 | 135.1 | 0.6 | 50 | 2880.8 | 2880.77 | 0.572949 | 0.0070735 | 4.2441
BEAM | +3.156 | +3.229 | 4.1 | 135.1 | 0.6 | 50 | 2880.8 | 2880.76 | 0.572941 | 0.00707335 | 4.24401
BEAM | +3.156 | +3.230 | 4.1 | 135.1 | 0.6 | 50 | 2880.8 | 2880.77 | 0.572949 | 0.0070735 | 4.2441
BEAM | +3.156 | +3.230 | 4.1 | 135.1 | 0.6 | 50 | 2880.8 | 2880.76 | 0.572941 | 0.00707335 | 4.24401
2 x BEAM | +3.157 | +3.231 | 4.1 | 135.1 | 0.6 | 50 | 2880.8 | 2880.77 | 0.572949 | 0.0070735 | 4.2441
2 x BEAM | +3.157 | +3.231 | 4.1 | 135.1 | 0.6 | 50 | 2880.8 | 2880.76 | 0.572941 | 0.00707335 | 4.24401
BEAM | +3.158 | +3.232 | 4.1 | 135.1 | 0.6 | 50 | 2880.8 | 2880.77 | 0.572949 | 0.0070735 | 4.2441
BEAM | +3.158 | +3.232 | 4.1 | 135.1 | 0.6 | 50 | 2880.8 | 2880.76 | 0.572941 | 0.00707335 | 4.24401
BEAM | +3.158 | +3.233 | 4.1 | 135.1 | 0.6 | 50 | 2880.8 | 2880.77 | 0.572949 | 0.0070735 | 4.2441
BEAM | +3.158 | +3.233 | 4.1 | 135.1 | 0.6 | 50 | 2880.8 | 2880.76 | 0.572941 | 0.00707335 | 4.24401
2 x BEAM | +3.159 | +3.234 | 4.1 | 135.1 | 0.6 | 50 | 2880.8 | 2880.77 | 0.572949 | 0.0070735 | 4.2441
2 x BEAM | +3.159 | +3.234 | 4.1 | 135.1 | 0.6 | 50 | 2880.8 | 2880.76 | 0.572941 | 0.00707335 | 4.24401
BEAM | +3.160 | +3.235 | 4.1 | 135.1 | 0.6 | 50 | 2880.8 | 2880.77 | 0.572949 | 0.0070735 | 4.2441
BEAM | +3.160 | +3.235 | 4.1 | 135.1 | 0.6 | 50 | 2880.8 | 2880.76 | 0.572941 | 0.00707335 | 4.24401
2 x BEAM | +3.160 | +3.236 | 4.1 | 135.1 | 0.6 | 50 | 2880.8 | 2880.77 | 0.572949 | 0.0070735 | 4.2441
2 x BEAM | +3.160 | +3.236 | 4.1 | 135.1 | 0.6 | 50 | 2880.8 | 2880.76 | 0.572941 | 0.00707335 | 4.24401
2 x BEAM | +3.161 | +3.237 | 4.1 | 135.1 | 0.6 | 50 | 2880.8 | 2880.77 | 0.572949 | 0.0070735 | 4.2441
2 x BEAM | +3.161 | +3.237 | 4.1 | 135.1 | 0.6 | 50 | 2880.8 | 2880.76 | 0.572941 | 0.00707335 | 4.24401
BEAM | +3.162 | +3.238 | 4.1 | 135.1 | 0.6 | 50 | 2880.8 | 2880.77 | 0.572949 | 0.0070735 | 4.2441
BEAM | +3.162 | +3.238 | 4.1 | 135.1 | 0.6 | 50 | 2880.8 | 2880.76 | 0.572941 | 0.00707335 | 4.24401
2 x BEAM | +3.162 | +3.239 | 4.1 | 135.1 | 0.6 | 50 | 2880.8 | 2880.77 | 0.572949 | 0.0070735 | 4.2441
2 x BEAM | +3.162 | +3.239 | 4.1 | 135.1 | 0.6 | 50 | 2880.8 | 2880.76 | 0.572941 | 0.00707335 | 4.24401
2 x BEAM | +3.163 | +3.240 | 4.1 | 135.1 | 0.6 | 50 | 2880.8 | 2880.77 | 0.572949 | 0.0070735 | 4.2441
2 x BEAM | +3.163 | +3.240 | 4.1 | 135.1 | 0.6 | 50 | 2880.8 | 2880.76 | 0.572941 | 0.00707335 | 4.24401
BEAM | +3.163 | +3.241 | 4.1 | 135.1 | 0.6 | 50 | 2880.8 | 2880.77 | 0.572949 | 0.0070735 | 4.2441
BEAM | +3.163 | +3.241 | 4.1 | 135.1 | 0.6 | 50 | 2880.8 | 2880.76 | 0.572941 | 0.00707335 | 4.24401
2 x BEAM | +3.164 | +3.242 | 4.1 | 135.1 | 0.6 | 50 | 2880.8 | 2880.77 | 0.572949 | 0.0070735 | 4.2441
2 x BEAM | +3.164 | +3.242 | 4.1 | 135.1 | 0.6 | 50 | 2880.8 | 2880.76 | 0.572941 | 0.00707335 | 4.24401
BEAM | +3.164 | +3.243 | 4.1 | 135.1 | 0.6 | 50 | 2880.8 | 2880.77 | 0.572949 | 0.0070735 | 4.2441
BEAM | +3.164 | +3.243 | 4.1 | 135.1 | 0.6 | 50 | 2880.8 | 2880.76 | 0.572941 | 0.00707335 | 4.24401
BEAM | +3.165 | +3.243 | 4.1 | 135.1 | 0.6 | 50 | 2880.8 | 2880.77 | 0.572949 | 0.0070735 | 4.2441
BEAM | +3.165 | +3.243 | 4.1 | 135.1 | 0.6 | 50 | 2880.8 | 2880.76 | 0.572941 | 0.00707335 | 4.24401
2 x BEAM | +3.165 | +3.244 | 4.1 | 135.1 | 0.6 | 50 | 2880.8 | 2880.77 | 0.572949 | 0.0070735 | 4.2441
2 x BEAM | +3.165 | +3.244 | 4.1 | 135.1 | 0.6 | 50 | 2880.8 | 2880.76 | 0.572941 | 0.00707335 | 4.24401
2 x BEAM | +3.166 | +3.245 | 4.1 | 135.1 | 0.6 | 50 | 2880.8 | 2880.77 | 0.572949 | 0.0070735 | 4.2441
2 x BEAM | +3.166 | +3.245 | 4.1 | 135.1 | 0.6 | 50 | 2880.8 | 2880.76 | 0.572941 | 0.00707335 | 4.24401
BEAM | +3.166 | +3.246 | 4.1 | 135.1 | 0.6 | 50 | 2880.8 | 2880.77 | 0.572949 | 0.0070735 | 4.2441
BEAM | +3.166 | +3.246 | 4.1 | 135.1 | 0.6 | 50 | 2880.8 | 2880.76 | 0.572941 | 0.00707335 | 4.24401
BEAM | +3.167 | +3.246 | 4.1 | 135.1 | 0.6 | 50 | 2880.8 | 2880.77 | 0.572949 | 0.0070735 | 4.2441
BEAM | +3.167 | +3.246 | 4.1 | 135.1 | 0.6 | 50 | 2880.8 | 2880.76 | 0.572941 | 0.00707335 | 4.24401
2 x BEAM | +3.167 | +3.247 | 4.1 | 135.1 | 0.6 | 50 | 2880.8 | 2880.77 | 0.572949 | 0.0070735 | 4.2441
2 x BEAM | +3.167 | +3.247 | 4.1 | 135.1 | 0.6 | 50 | 2880.8 | 2880.76 | 0.572941 | 0.00707335 | 4.24401
BEAM | +3.167 | +3.248 | 4.1 | 135.1 | 0.6 | 50 | 2880.8 | 2880.77 | 0.572949 | 0.0070735 | 4.2441
BEAM | +3.167 | +3.248 | 4.1 | 135.1 | 0.6 | 50 | 2880.8 | 2880.76 | 0.572941 | 0.00707335 | 4.24401
BEAM | +3.168 | +3.248 | 4.1 | 135.1 | 0.6 | 50 | 2880.8 | 2880.77 | 0.572949 | 0.0070735 | 4.2441
BEAM | +3.168 | +3.248 | 4.1 | 135.1 | 0.6 | 50 | 2880.8 | 2880.76 | 0.572941 | 0.00707335 | 4.24401
2 x BEAM | +3.168 | +3.249 | 4.1 | 135.1 | 0.6 | 50 | 2880.8 | 2880.77 | 0.572949 | 0.0070735 | 4.2441
2 x BEAM | +3.168 | +3.249 | 4.1 | 135.1 | 0.6 | 50 | 2880.8 | 2880.76 | 0.572941 | 0.00707335 | 4.24401
2 x BEAM | +3.168 | +3.250 | 4.1 | 135.1 | 0.6 | 50 | 2880.8 | 2880.77 | 0.572949 | 0.0070735 | 4.2441
2 x BEAM | +3.168 | +3.250 | 4.1 | 135.1 | 0.6 | 50 | 2880.8 | 2880.76 | 0.572941 | 0.00707335 | 4.24401
3 x BEAM | +3.169 | +3.251 | 4.1 | 135.1 | 0.6 | 50 | 2880.8 | 2880.77 | 0.572949 | 0.0070735 | 4.2441
3 x BEAM | +3.169 | +3.251 | 4.1 | 135.1 | 0.6 | 50 | 2880.8 | 2880.76 | 0.572941 | 0.00707335 | 4.24401
2 x BEAM | +3.169 | +3.252 | 4.1 | 135.1 | 0.6 | 50 | 2880.8 | 2880.77 | 0.572949 | 0.0070735 | 4.2441
2 x BEAM | +3.169 | +3.252 | 4.1 | 135.1 | 0.6 | 50 | 2880.8 | 2880.76 | 0.572941 | 0.00707335 | 4.24401
BEAM | +3.169 | +3.253 | 4.1 | 135.1 | 0.6 | 50 | 2880.8 | 2880.77 | 0.572949 | 0.0070735 | 4.2441
BEAM | +3.169 | +3.253 | 4.1 | 135.1 | 0.6 | 50 | 2880.8 | 2880.76 | 0.572941 | 0.00707335 | 4.24401
2 x BEAM | +3.170 | +3.253 | 4.1 | 135.1 | 0.6 | 50 | 2880.8 | 2880.77 | 0.572949 | 0.0070735 | 4.2441
2 x BEAM | +3.170 | +3.253 | 4.1 | 135.1 | 0.6 | 50 | 2880.8 | 2880.76 | 0.572941 | 0.00707335 | 4.24401
3 x BEAM | +3.170 | +3.254 | 4.1 | 135.1 | 0.6 | 50 | 2880.8 | 2880.77 | 0.572949 | 0.0070735 | 4.2441
3 x BEAM | +3.170 | +3.254 | 4.1 | 135.1 | 0.6 | 50 | 2880.8 | 2880.76 | 0.572941 | 0.00707335 | 4.24401
3 x BEAM | +3.170 | +3.255 | 4.1 | 135.1 | 0.6 | 50 | 2880.8 | 2880.77 | 0.572949 | 0.0070735 | 4.2441
3 x BEAM | +3.170 | +3.255 | 4.1 | 135.1 | 0.6 | 50 | 2880.8 | 2880.76 | 0.572941 | 0.00707335 | 4.24401
BEAM | +3.170 | +3.256 | 4.1 | 135.1 | 0.6 | 50 | 2880.8 | 2880.77 | 0.572949 | 0.0070735 | 4.2441
BEAM | +3.170 | +3.256 | 4.1 | 135.1 | 0.6 | 50 | 2880.8 | 2880.76 | 0.572941 | 0.00707335 | 4.24401
3 x BEAM | +3.171 | +3.256 | 4.1 | 135.1 | 0.6 | 50 | 2880.8 | 2880.77 | 0.572949 | 0.0070735 | 4.2441
3 x BEAM | +3.171 | +3.256 | 4.1 | 135.1 | 0.6 | 50 | 2880.8 | 2880.76 | 0.572941 | 0.00707335 | 4.24401
4 x BEAM | +3.171 | +3.257 | 4.1 | 135.1 | 0.6 | 50 | 2880.8 | 2880.77 | 0.572949 | 0.0070735 | 4.2441
4 x BEAM | +3.171 | +3.257 | 4.1 | 135.1 | 0.6 | 50 | 2880.8 | 2880.76 | 0.572941 | 0.00707335 | 4.24401
4 x BEAM | +3.171 | +3.258 | 4.1 | 135.1 | 0.6 | 50 | 2880.8 | 2880.77 | 0.572949 | 0.0070735 | 4.2441
4 x BEAM | +3.171 | +3.258 | 4.1 | 135.1 | 0.6 | 50 | 2880.8 | 2880.76 | 0.572941 | 0.00707335 | 4.24401
5 x BEAM | +3.171 | +3.259 | 4.1 | 135.1 | 0.6 | 50 | 2880.8 | 2880.77 | 0.572949 | 0.0070735 | 4.2441
5 x BEAM | +3.171 | +3.259 | 4.1 | 135.1 | 0.6 | 50 | 2880.8 | 2880.76 | 0.572941 | 0.00707335 | 4.24401
BEAM | +3.171 | +3.260 | 4.1 | 135.1 | 0.6 | 50 | 2880.8 | 2880.77 | 0.572949 | 0.0070735 | 4.2441
BEAM | +3.171 | +3.260 | 4.1 | 135.1 | 0.6 | 50 | 2880.8 | 2880.76 | 0.572941 | 0.00707335 | 4.24401
7 x BEAM | +3.170 | +3.260 | 4.1 | 135.1 | 0.6 | 50 | 2880.8 | 2880.77 | 0.572949 | 0.0070735 | 4.2441
7 x BEAM | +3.170 | +3.260 | 4.1 | 135.1 | 0.6 | 50 | 2880.8 | 2880.76 | 0.572941 | 0.00707335 | 4.24401
2 x BEAM | +3.170 | +3.261 | 4.1 | 135.1 | 0.6 | 50 | 2880.8 | 2880.77 | 0.572949 | 0.0070735 | 4.2441
2 x BEAM | +3.170 | +3.261 | 4.1 | 135.1 | 0.6 | 50 | 2880.8 | 2880.76 | 0.572941 | 0.00707335 | 4.24401
6 x BEAM | +3.169 | +3.261 | 4.1 | 135.1 | 0.6 | 50 | 2880.8 | 2880.77 | 0.572949 | 0.0070735 | 4.2441
6 x BEAM | +3.169 | +3.261 | 4.1 | 135.1 | 0.6 | 50 | 2880.8 | 2880.76 | 0.572941 | 0.00707335 | 4.24401
4 x BEAM | +3.168 | +3.261 | 4.1 | 135.1 | 0.6 | 50 | 2880.8 | 2880.77 | 0.572949 | 0.0070735 | 4.2441
4 x BEAM | +3.168 | +3.261 | 4.1 | 135.1 | 0.6 | 50 | 2880.8 | 2880.76 | 0.572941 | 0.00707335 | 4.24401
4 x BEAM | +3.167 | +3.261 | 4.1 | 135.1 | 0.6 | 50 | 2880.8 | 2880.77 | 0.572949 | 0.0070735 | 4.2441
4 x BEAM | +3.167 | +3.261 | 4.1 | 135.1 | 0.6 | 50 | 2880.8 | 2880.76 | 0.572941 | 0.00707335 | 4.24401
4 x BEAM | +3.166 | +3.261 | 4.1 | 135.1 | 0.6 | 50 | 2880.8 | 2880.77 | 0.572949 | 0.0070735 | 4.2441
4 x BEAM | +3.166 | +3.261 | 4.1 | 135.1 | 0.6 | 50 | 2880.8 | 2880.76 | 0.572941 | 0.00707335 | 4.24401
3 x BEAM | +3.165 | +3.261 | 4.1 | 135.1 | 0.6 | 50 | 2880.8 | 2880.77 | 0.572949 | 0.0070735 | 4.2441
3 x BEAM | +3.165 | +3.261 | 4.1 | 135.1 | 0.6 | 50 | 2880.8 | 2880.76 | 0.572941 | 0.00707335 | 4.24401
3 x BEAM | +3.164 | +3.261 | 4.1 | 135.1 | 0.6 | 50 | 2880.8 | 2880.77 | 0.572949 | 0.0070735 | 4.2441
3 x BEAM | +3.164 | +3.261 | 4.1 | 135.1 | 0.6 | 50 | 2880.8 | 2880.76 | 0.572941 | 0.00707335 | 4.24401
3 x BEAM | +3.163 | +3.260 | 4.1 | 135.1 | 0.6 | 50 | 2880.8 | 2880.77 | 0.572949 | 0.0070735 | 4.2441
3 x BEAM | +3.163 | +3.260 | 4.1 | 135.1 | 0.6 | 50 | 2880.8 | 2880.76 | 0.572941 | 0.00707335 | 4.24401
2 x BEAM | +3.162 | +3.260 | 4.1 | 135.1 | 0.6 | 50 | 2880.8 | 2880.77 | 0.572949 | 0.0070735 | 4.2441
2 x BEAM | +3.162 | +3.260 | 4.1 | 135.1 | 0.6 | 50 | 2880.8 | 2880.76 | 0.572941 | 0.00707335 | 4.24401
2 x BEAM | +3.161 | +3.260 | 4.1 | 135.1 | 0.6 | 50 | 2880.8 | 2880.77 | 0.572949 | 0.0070735 | 4.2441
2 x BEAM | +3.161 | +3.260 | 4.1 | 135.1 | 0.6 | 50 | 2880.8 | 2880.76 | 0.572941 | 0.00707335 | 4.24401
BEAM | +3.161 | +3.259 | 4.1 | 135.1 | 0.6 | 50 | 2880.8 | 2880.77 | 0.572949 | 0.0070735 | 4.2441
BEAM | +3.161 | +3.259 | 4.1 | 135.1 | 0.6 | 50 | 2880.8 | 2880.76 | 0.572941 | 0.00707335 | 4.24401
2 x BEAM | +3.160 | +3.259 | 4.1 | 135.1 | 0.6 | 50 | 2880.8 | 2880.77 | 0.572949 | 0.0070735 | 4.2441
2 x BEAM | +3.160 | +3.259 | 4.1 | 135.1 | 0.6 | 50 | 2880.8 | 2880.76 | 0.572941 | 0.00707335 | 4.24401
2 x BEAM | +3.159 | +3.259 | 4.1 | 135.1 | 0.6 | 50 | 2880.8 | 2880.77 | 0.572949 | 0.0070735 | 4.2441
2 x BEAM | +3.159 | +3.259 | 4.1 | 135.1 | 0.6 | 50 | 2880.8 | 2880.76 | 0.572941 | 0.00707335 | 4.24401
2 x BEAM | +3.158 | +3.258 | 4.1 | 135.1 | 0.6 | 50 | 2880.8 | 2880.77 | 0.572949 | 0.0070735 | 4.2441
2 x BEAM | +3.158 | +3.258 | 4.1 | 135.1 | 0.6 | 50 | 2880.8 | 2880.76 | 0.572941 | 0.00707335 | 4.24401
3 x BEAM | +3.157 | +3.258 | 4.1 | 135.1 | 0.6 | 50 | 2880.8 | 2880.77 | 0.572949 | 0.0070735 | 4.2441
3 x BEAM | +3.157 | +3.258 | 4.1 | 135.1 | 0.6 | 50 | 2880.8 | 2880.76 | 0.572941 | 0.00707335 | 4.24401
2 x BEAM | +3.156 | +3.257 | 4.1 | 135.1 | 0.6 | 50 | 2880.8 | 2880.77 | 0.572949 | 0.0070735 | 4.2441
2 x BEAM | +3.156 | +3.257 | 4.1 | 135.1 | 0.6 | 50 | 2880.8 | 2880.76 | 0.572941 | 0.00707335 | 4.24401
BEAM | +3.155 | +3.257 | 4.1 | 135.1 | 0.6 | 50 | 2880.8 | 2880.77 | 0.572949 | 0.0070735 | 4.2441
BEAM | +3.155 | +3.257 | 4.1 | 135.1 | 0.6 | 50 | 2880.8 | 2880.76 | 0.572941 | 0.00707335 | 4.24401
BEAM | +3.154 | +3.257 | 4.1 | 135.1 | 0.6 | 50 | 2880.8 | 2880.77 | 0.572949 | 0.0070735 | 4.2441
BEAM | +3.154 | +3.257 | 4.1 | 135.1 | 0.6 | 50 | 2880.8 | 2880.76 | 0.572941 | 0.00707335 | 4.24401
BEAM | +3.154 | +3.256 | 4.1 | 135.1 | 0.6 | 50 | 2880.8 | 2880.77 | 0.572949 | 0.0070735 | 4.2441
BEAM | +3.154 | +3.256 | 4.1 | 135.1 | 0.6 | 50 | 2880.8 | 2880.76 | 0.572941 | 0.00707335 | 4.24401
2 x BEAM | +3.153 | +3.256 | 4.1 | 135.1 | 0.6 | 50 | 2880.8 | 2880.77 | 0.572949 | 0.0070735 | 4.2441
2 x BEAM | +3.153 | +3.256 | 4.1 | 135.1 | 0.6 | 50 | 2880.8 | 2880.76 | 0.572941 | 0.00707335 | 4.24401
2 x BEAM | +3.152 | +3.255 | 4.1 | 135.1 | 0.6 | 50 | 2880.8 | 2880.77 | 0.572949 | 0.0070735 | 4.2441
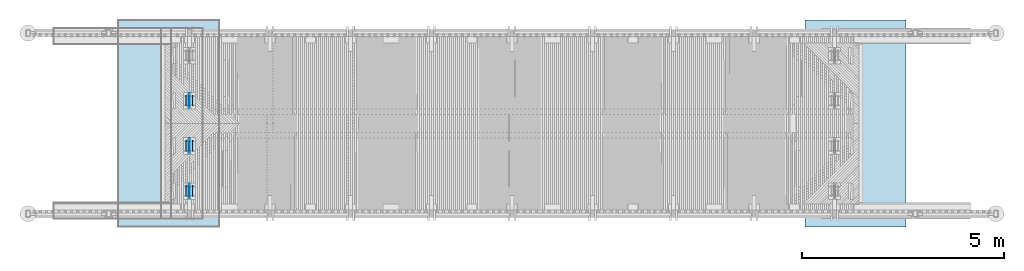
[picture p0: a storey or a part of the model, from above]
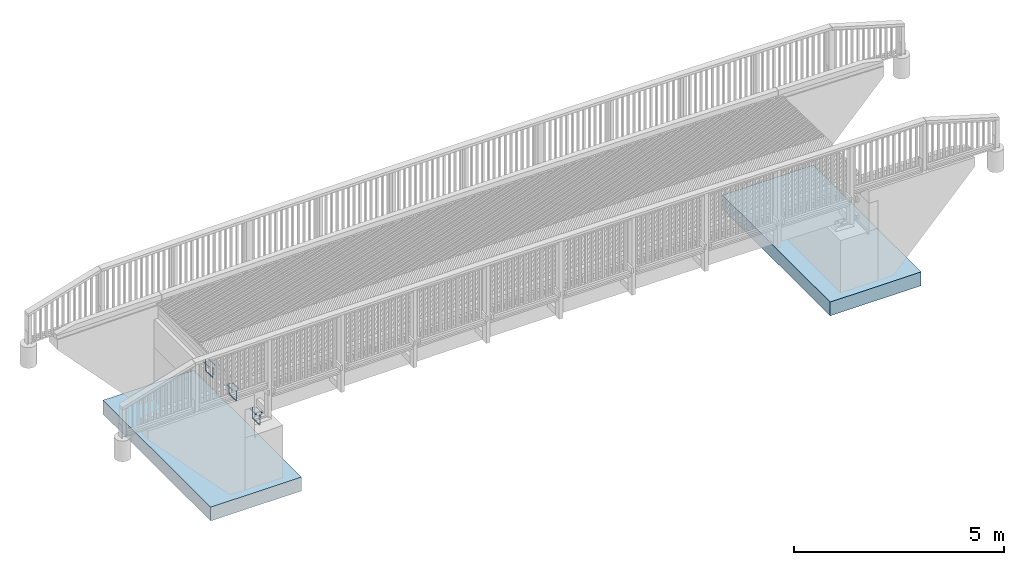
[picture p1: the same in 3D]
Properties of the parts of a building model (IFC2X3), part 2 of 2

# IfcBeam: 50*50 (546)
Name | Bottom elevation | Top elevation | Weight (kg) | Area per tons (m2) | Net surface area (m2) | Height (mm) | Tekla Quantity, Length (mm) | BaseQuantities, Length (mm) | OuterSurfaceArea (m2) | NetVolume (m3) | NetWeight (kg)
2 x BEAM | +3.152 | +3.255 | 4.1 | 135.1 | 0.6 | 50 | 2880.8 | 2880.76 | 0.572941 | 0.00707335 | 4.24401
BEAM | +3.151 | +3.255 | 4.1 | 135.1 | 0.6 | 50 | 2880.8 | 2880.77 | 0.572949 | 0.0070735 | 4.2441
BEAM | +3.151 | +3.255 | 4.1 | 135.1 | 0.6 | 50 | 2880.8 | 2880.76 | 0.572941 | 0.00707335 | 4.24401
BEAM | +3.151 | +3.254 | 4.1 | 135.1 | 0.6 | 50 | 2880.8 | 2880.77 | 0.572949 | 0.0070735 | 4.2441
BEAM | +3.151 | +3.254 | 4.1 | 135.1 | 0.6 | 50 | 2880.8 | 2880.76 | 0.572941 | 0.00707335 | 4.24401
BEAM | +3.150 | +3.254 | 4.1 | 135.1 | 0.6 | 50 | 2880.8 | 2880.77 | 0.572949 | 0.0070735 | 4.2441
BEAM | +3.150 | +3.254 | 4.1 | 135.1 | 0.6 | 50 | 2880.8 | 2880.76 | 0.572941 | 0.00707335 | 4.24401
BEAM | +3.149 | +3.254 | 4.1 | 135.1 | 0.6 | 50 | 2880.8 | 2880.77 | 0.572949 | 0.0070735 | 4.2441
BEAM | +3.149 | +3.254 | 4.1 | 135.1 | 0.6 | 50 | 2880.8 | 2880.76 | 0.572941 | 0.00707335 | 4.24401
BEAM | +3.149 | +3.253 | 4.1 | 135.1 | 0.6 | 50 | 2880.8 | 2880.77 | 0.572949 | 0.0070735 | 4.2441
BEAM | +3.149 | +3.253 | 4.1 | 135.1 | 0.6 | 50 | 2880.8 | 2880.76 | 0.572941 | 0.00707335 | 4.24401
2 x BEAM | +3.148 | +3.253 | 4.1 | 135.1 | 0.6 | 50 | 2880.8 | 2880.77 | 0.572949 | 0.0070735 | 4.2441
2 x BEAM | +3.148 | +3.253 | 4.1 | 135.1 | 0.6 | 50 | 2880.8 | 2880.76 | 0.572941 | 0.00707335 | 4.24401
BEAM | +3.147 | +3.252 | 4.1 | 135.1 | 0.6 | 50 | 2880.8 | 2880.77 | 0.572949 | 0.0070735 | 4.2441
BEAM | +3.147 | +3.252 | 4.1 | 135.1 | 0.6 | 50 | 2880.8 | 2880.76 | 0.572941 | 0.00707335 | 4.24401
BEAM | +3.146 | +3.252 | 4.1 | 135.1 | 0.6 | 50 | 2880.8 | 2880.77 | 0.572949 | 0.0070735 | 4.2441
BEAM | +3.146 | +3.252 | 4.1 | 135.1 | 0.6 | 50 | 2880.8 | 2880.76 | 0.572941 | 0.00707335 | 4.24401
BEAM | +3.146 | +3.251 | 4.1 | 135.1 | 0.6 | 50 | 2880.8 | 2880.77 | 0.572949 | 0.0070735 | 4.2441
BEAM | +3.146 | +3.251 | 4.1 | 135.1 | 0.6 | 50 | 2880.8 | 2880.76 | 0.572941 | 0.00707335 | 4.24401
BEAM | +3.145 | +3.251 | 4.1 | 135.1 | 0.6 | 50 | 2880.8 | 2880.77 | 0.572949 | 0.0070735 | 4.2441
BEAM | +3.145 | +3.251 | 4.1 | 135.1 | 0.6 | 50 | 2880.8 | 2880.76 | 0.572941 | 0.00707335 | 4.24401
BEAM | +3.144 | +3.251 | 4.1 | 135.1 | 0.6 | 50 | 2880.8 | 2880.77 | 0.572949 | 0.0070735 | 4.2441
BEAM | +3.144 | +3.251 | 4.1 | 135.1 | 0.6 | 50 | 2880.8 | 2880.76 | 0.572941 | 0.00707335 | 4.24401
BEAM | +3.144 | +3.250 | 4.1 | 135.1 | 0.6 | 50 | 2880.8 | 2880.77 | 0.572949 | 0.0070735 | 4.2441
BEAM | +3.144 | +3.250 | 4.1 | 135.1 | 0.6 | 50 | 2880.8 | 2880.76 | 0.572941 | 0.00707335 | 4.24401
BEAM | +3.143 | +3.250 | 4.1 | 135.1 | 0.6 | 50 | 2880.8 | 2880.77 | 0.572949 | 0.0070735 | 4.2441
BEAM | +3.143 | +3.250 | 4.1 | 135.1 | 0.6 | 50 | 2880.8 | 2880.76 | 0.572941 | 0.00707335 | 4.24401
2 x BEAM | +3.142 | +3.249 | 4.1 | 135.1 | 0.6 | 50 | 2880.8 | 2880.77 | 0.572949 | 0.0070735 | 4.2441
2 x BEAM | +3.142 | +3.249 | 4.1 | 135.1 | 0.6 | 50 | 2880.8 | 2880.76 | 0.572941 | 0.00707335 | 4.24401
BEAM | +3.141 | +3.248 | 4.1 | 135.1 | 0.6 | 50 | 2880.8 | 2880.77 | 0.572949 | 0.0070735 | 4.2441
BEAM | +3.141 | +3.248 | 4.1 | 135.1 | 0.6 | 50 | 2880.8 | 2880.76 | 0.572941 | 0.00707335 | 4.24401
BEAM | +3.140 | +3.248 | 4.1 | 135.1 | 0.6 | 50 | 2880.8 | 2880.77 | 0.572949 | 0.0070735 | 4.2441
BEAM | +3.140 | +3.248 | 4.1 | 135.1 | 0.6 | 50 | 2880.8 | 2880.76 | 0.572941 | 0.00707335 | 4.24401
BEAM | +3.140 | +3.247 | 4.1 | 135.1 | 0.6 | 50 | 2880.8 | 2880.77 | 0.572949 | 0.0070735 | 4.2441
BEAM | +3.140 | +3.247 | 4.1 | 135.1 | 0.6 | 50 | 2880.8 | 2880.76 | 0.572941 | 0.00707335 | 4.24401
BEAM | +3.139 | +3.247 | 4.1 | 135.1 | 0.6 | 50 | 2880.8 | 2880.77 | 0.572949 | 0.0070735 | 4.2441
BEAM | +3.139 | +3.247 | 4.1 | 135.1 | 0.6 | 50 | 2880.8 | 2880.76 | 0.572941 | 0.00707335 | 4.24401
BEAM | +3.138 | +3.246 | 4.1 | 135.1 | 0.6 | 50 | 2880.8 | 2880.77 | 0.572949 | 0.0070735 | 4.2441
BEAM | +3.138 | +3.246 | 4.1 | 135.1 | 0.6 | 50 | 2880.8 | 2880.76 | 0.572941 | 0.00707335 | 4.24401
BEAM | +3.137 | +3.246 | 4.1 | 135.1 | 0.6 | 50 | 2880.8 | 2880.77 | 0.572949 | 0.0070735 | 4.2441
BEAM | +3.137 | +3.246 | 4.1 | 135.1 | 0.6 | 50 | 2880.8 | 2880.76 | 0.572941 | 0.00707335 | 4.24401
BEAM | +3.137 | +3.245 | 4.1 | 135.1 | 0.6 | 50 | 2880.8 | 2880.77 | 0.572949 | 0.0070735 | 4.2441
BEAM | +3.137 | +3.245 | 4.1 | 135.1 | 0.6 | 50 | 2880.8 | 2880.76 | 0.572941 | 0.00707335 | 4.24401
BEAM | +3.136 | +3.245 | 4.1 | 135.1 | 0.6 | 50 | 2880.8 | 2880.77 | 0.572949 | 0.0070735 | 4.2441
BEAM | +3.136 | +3.245 | 4.1 | 135.1 | 0.6 | 50 | 2880.8 | 2880.76 | 0.572941 | 0.00707335 | 4.24401
BEAM | +3.135 | +3.244 | 4.1 | 135.1 | 0.6 | 50 | 2880.8 | 2880.77 | 0.572949 | 0.0070735 | 4.2441
BEAM | +3.135 | +3.244 | 4.1 | 135.1 | 0.6 | 50 | 2880.8 | 2880.76 | 0.572941 | 0.00707335 | 4.24401
BEAM | +3.134 | +3.244 | 4.1 | 135.1 | 0.6 | 50 | 2880.8 | 2880.77 | 0.572949 | 0.0070735 | 4.2441
BEAM | +3.134 | +3.244 | 4.1 | 135.1 | 0.6 | 50 | 2880.8 | 2880.76 | 0.572941 | 0.00707335 | 4.24401
BEAM | +3.134 | +3.243 | 4.1 | 135.1 | 0.6 | 50 | 2880.8 | 2880.77 | 0.572949 | 0.0070735 | 4.2441
BEAM | +3.134 | +3.243 | 4.1 | 135.1 | 0.6 | 50 | 2880.8 | 2880.76 | 0.572941 | 0.00707335 | 4.24401
BEAM | +3.133 | +3.243 | 4.1 | 135.1 | 0.6 | 50 | 2880.8 | 2880.77 | 0.572949 | 0.0070735 | 4.2441
BEAM | +3.133 | +3.243 | 4.1 | 135.1 | 0.6 | 50 | 2880.8 | 2880.76 | 0.572941 | 0.00707335 | 4.24401
BEAM | +3.132 | +3.242 | 4.1 | 135.1 | 0.6 | 50 | 2880.8 | 2880.77 | 0.572949 | 0.0070735 | 4.2441
BEAM | +3.132 | +3.242 | 4.1 | 135.1 | 0.6 | 50 | 2880.8 | 2880.76 | 0.572941 | 0.00707335 | 4.24401
BEAM | +3.131 | +3.242 | 4.1 | 135.1 | 0.6 | 50 | 2880.8 | 2880.77 | 0.572949 | 0.0070735 | 4.2441
BEAM | +3.131 | +3.242 | 4.1 | 135.1 | 0.6 | 50 | 2880.8 | 2880.76 | 0.572941 | 0.00707335 | 4.24401
BEAM | +3.130 | +3.241 | 4.1 | 135.1 | 0.6 | 50 | 2880.8 | 2880.77 | 0.572949 | 0.0070735 | 4.2441
BEAM | +3.130 | +3.241 | 4.1 | 135.1 | 0.6 | 50 | 2880.8 | 2880.76 | 0.572941 | 0.00707335 | 4.24401
BEAM | +3.129 | +3.241 | 4.1 | 135.1 | 0.6 | 50 | 2880.8 | 2880.77 | 0.572949 | 0.0070735 | 4.2441
BEAM | +3.129 | +3.241 | 4.1 | 135.1 | 0.6 | 50 | 2880.8 | 2880.76 | 0.572941 | 0.00707335 | 4.24401
BEAM | +3.129 | +3.240 | 4.1 | 135.1 | 0.6 | 50 | 2880.8 | 2880.77 | 0.572949 | 0.0070735 | 4.2441
BEAM | +3.129 | +3.240 | 4.1 | 135.1 | 0.6 | 50 | 2880.8 | 2880.76 | 0.572941 | 0.00707335 | 4.24401
BEAM | +3.128 | +3.239 | 4.1 | 135.1 | 0.6 | 50 | 2880.8 | 2880.77 | 0.572949 | 0.0070735 | 4.2441
BEAM | +3.128 | +3.239 | 4.1 | 135.1 | 0.6 | 50 | 2880.8 | 2880.76 | 0.572941 | 0.00707335 | 4.24401
BEAM | +3.127 | +3.239 | 4.1 | 135.1 | 0.6 | 50 | 2880.8 | 2880.77 | 0.572949 | 0.0070735 | 4.2441
BEAM | +3.127 | +3.239 | 4.1 | 135.1 | 0.6 | 50 | 2880.8 | 2880.76 | 0.572941 | 0.00707335 | 4.24401
BEAM | +3.126 | +3.238 | 4.1 | 135.1 | 0.6 | 50 | 2880.8 | 2880.77 | 0.572949 | 0.0070735 | 4.2441
BEAM | +3.126 | +3.238 | 4.1 | 135.1 | 0.6 | 50 | 2880.8 | 2880.76 | 0.572941 | 0.00707335 | 4.24401
BEAM | +3.125 | +3.237 | 4.1 | 135.1 | 0.6 | 50 | 2880.8 | 2880.77 | 0.572949 | 0.0070735 | 4.2441
BEAM | +3.125 | +3.237 | 4.1 | 135.1 | 0.6 | 50 | 2880.8 | 2880.76 | 0.572941 | 0.00707335 | 4.24401
BEAM | +3.124 | +3.237 | 4.1 | 135.1 | 0.6 | 50 | 2880.8 | 2880.77 | 0.572949 | 0.0070735 | 4.2441
BEAM | +3.124 | +3.237 | 4.1 | 135.1 | 0.6 | 50 | 2880.8 | 2880.76 | 0.572941 | 0.00707335 | 4.24401

# IfcBeam: 70*70 (48)
In: Undefined
Description: 70*70; Material: TIMBER/Timber_Undefined
Tekla Common - Phase: 600; Class: 1
Tekla Quantity - Volume: 0 m3; Gross footprint area: 0 m2; Height: 70 mm; Width: 70 mm
Pset_BeamCommon - LoadBearing: yes; Reference: P/0(?)
Name | Bottom elevation | Top elevation | Weight (kg) | Area per tons (m2) | Net surface area (m2) | Tekla Quantity, Length (mm) | BaseQuantities, Length (mm) | OuterSurfaceArea (m2) | NetVolume (m3) | NetWeight (kg)
4 x BEAM | +3.840 | +4.475 | 5.8 | 97 | 0.6 | 1982.9 | 1982.9 | 0.559589 | 0.00961382 | 5.76829
4 x BEAM | +3.121 | +3.219 | 5.4 | 97.1 | 0.5 | 1820.2 | 1820.22 | 0.519462 | 0.00891908 | 5.35145
4 x BEAM | +3.152 | +3.250 | 5.4 | 97 | 0.5 | 1850.2 | 1850.22 | 0.527862 | 0.00906608 | 5.43965
4 x BEAM | +4.411 | +4.510 | 5.4 | 97 | 0.5 | 1880.2 | 1880.22 | 0.536262 | 0.00921308 | 5.52785
4 x BEAM | +2.880 | +2.973 | 5.4 | 97 | 0.5 | 1880.2 | 1880.14 | 0.53624 | 0.00921269 | 5.52762
4 x BEAM | +2.904 | +2.990 | 5.4 | 97 | 0.5 | 1880.2 | 1880.07 | 0.53622 | 0.00921235 | 5.52741
2 x BEAM | +2.920 | +3.000 | 5.4 | 97 | 0.5 | 1880 | 1880.03 | 0.536207 | 0.00921213 | 5.52728
4 x BEAM | +2.930 | +3.003 | 5.4 | 97 | 0.5 | 1880 | 1880 | 0.536201 | 0.00921201 | 5.52721
2 x BEAM | +2.917 | +2.997 | 5.4 | 97 | 0.5 | 1880 | 1880.03 | 0.536207 | 0.00921213 | 5.52728
4 x BEAM | +4.440 | +4.533 | 5.4 | 97 | 0.5 | 1880.2 | 1880.14 | 0.53624 | 0.00921269 | 5.52762
4 x BEAM | +4.464 | +4.550 | 5.4 | 97 | 0.5 | 1880.2 | 1880.07 | 0.53622 | 0.00921235 | 5.52741
2 x BEAM | +4.480 | +4.560 | 5.4 | 97 | 0.5 | 1880 | 1880.03 | 0.536207 | 0.00921213 | 5.52728
4 x BEAM | +4.490 | +4.563 | 5.4 | 97 | 0.5 | 1880 | 1880 | 0.536201 | 0.00921201 | 5.52721
2 x BEAM | +4.477 | +4.557 | 5.4 | 97 | 0.5 | 1880 | 1880.03 | 0.536207 | 0.00921213 | 5.52728

# IfcBeam: 810*250 (2)
In: Undefined
Description: 810*250; Material: CONCRETE/Concrete_Undefined
Pset_BeamCommon - LoadBearing: yes; Reference: Concrete_LP-1001/0(?)
Tekla Common - Bottom elevation: +1.924; Top elevation: +2.734; Phase: 100; Class: 1009
Tekla Quantity - Weight: 2298.8 kg; Volume: 1 m3; Gross footprint area: 1.2 m2; Area per tons: 4.5 m2; Net surface area: 10.4 m2; Height: 810 mm; Width: 250 mm; Length: 4730 mm
BaseQuantities - Length: 4730 mm; OuterSurfaceArea: 10.4326 m2; NetVolume: 0.957825 m3; NetWeight: 2298.78 kg

# IfcBeam: 945*140 (9)
In: Undefined
Description: 945*140; Material: TIMBER/Timber_Undefined
Tekla Common - Phase: 600; Class: 4011
Tekla Quantity - Weight: 71.8 kg; Volume: 0.1 m3; Gross footprint area: 0.1 m2; Area per tons: 31 m2; Net surface area: 2.2 m2; Height: 945 mm; Width: 140 mm; Length: 905 mm
Pset_BeamCommon - LoadBearing: yes; Reference: PP/0(?)
BaseQuantities - Length: 905 mm; OuterSurfaceArea: 2.22845 m2; NetVolume: 0.119732 m3; NetWeight: 71.8389 kg
Name | Bottom elevation | Top elevation
2 x PALKKI | +2.030 | +2.975
4 x PALKKI | +2.028 | +2.973
3 x PALKKI | +2.070 | +3.015

# IfcBeam: 990*215 (4)
In: Undefined
Description: 990*215; Material: TIMBER/Timber_Undefined
Pset_BeamCommon - LoadBearing: yes; Reference: PP/0(?)
Tekla Common - Phase: 400; Class: 4011
Tekla Quantity - Weight: 2137.4 kg; Volume: 3.6 m3; Gross footprint area: 0.1 m2; Area per tons: 19.1 m2; Net surface area: 40.8 m2; Height: 990 mm; Width: 215 mm; Length: 16892.3 mm
BaseQuantities - Length: 16892.3 mm; OuterSurfaceArea: 40.8264 m2; NetVolume: 3.5623 m3; NetWeight: 2137.38 kg
Name | Bottom elevation | Top elevation
2 x PALKKI | +1.985 | +3.025
2 x PALKKI | +2.007 | +3.047

# IfcBeam: L100*10 (16)
In: Undefined
Description: L100*10; Material: STEEL/S235JR
Pset_BeamCommon - LoadBearing: yes; Reference: P/0(?)
Tekla Common - Phase: 600; Class: 1
Tekla Quantity - Weight: 4.5 kg; Volume: 0 m3; Gross footprint area: 0 m2; Area per tons: 25.9 m2; Net surface area: 0.1 m2; Height: 100 mm; Width: 100 mm; Length: 300 mm
BaseQuantities - Length: 300 mm; OuterSurfaceArea: 0.117 m2; NetVolume: 0.00057 m3; NetWeight: 4.4745 kg
Name | Bottom elevation | Top elevation
8 x BEAM | +1.997 | +2.097
8 x BEAM | +1.975 | +2.075

# IfcBeam: PL100*10 (8)
In: Undefined
Description: PL100*10; Material: STEEL/AISI316
Pset_BeamCommon - LoadBearing: yes; Reference: KPL/0(?)
Tekla Common - Phase: 600; Class: 8013
Tekla Quantity - Weight: 1.1 kg; Volume: 0 m3; Gross footprint area: 0 m2; Area per tons: 29.8 m2; Net surface area: 0 m2; Height: 100 mm; Width: 10 mm; Length: 140 mm
BaseQuantities - Length: 140 mm; OuterSurfaceArea: 0.0328 m2; NetVolume: 0.00014 m3; NetWeight: 1.099 kg
Name | Bottom elevation | Top elevation
4 x KAIDEPYLVÄS | +3.085 | +3.095
4 x KAIDEPYLVÄS | +3.113 | +3.123

# IfcBeam: PL60*10 (12)
In: Undefined
Description: PL60*10; Material: STEEL/AISI316
Tekla Common - Phase: 600; Class: 8013
Tekla Quantity - Weight: 0.5 kg; Volume: 0 m3; Gross footprint area: 0 m2; Area per tons: 31.9 m2; Net surface area: 0 m2; Height: 60 mm; Width: 10 mm; Length: 115 mm
Pset_BeamCommon - LoadBearing: yes; Reference: KPL/0(?)
BaseQuantities - Length: 115 mm; OuterSurfaceArea: 0.0173 m2; NetVolume: 0.000069 m3; NetWeight: 0.54165 kg
Name | Bottom elevation | Top elevation
4 x KAIDEPYLVÄS | +3.069 | +3.079
8 x KAIDEPYLVÄS | +3.097 | +3.107

# IfcColumn: 180*100 (26)
In: Undefined
Description: 180*100; Material: TIMBER/Timber_Undefined
Tekla Common - Phase: 600; Class: 8013
Tekla Quantity - Volume: 0 m3; Gross footprint area: 0 m2; Height: 180 mm; Width: 100 mm
Pset_ColumnCommon - LoadBearing: yes; Reference: KPP/0(?)
Name | Bottom elevation | Top elevation | Weight (kg) | Area per tons (m2) | Net surface area (m2) | Tekla Quantity, Length (mm) | BaseQuantities, Length (mm) | OuterSurfaceArea (m2) | NetVolume (m3) | NetWeight (kg)
4 x KAIDEPYLVÄS | +3.095 | +3.910 | 8.7 | 56.1 | 0.5 | 815.8 | 815.84 | 0.485338 | 0.0144181 | 8.65086
4 x KAIDEPYLVÄS | +3.123 | +4.481 | 14.7 | 54.3 | 0.8 | 1358.6 | 1358.59 | 0.796347 | 0.0244396 | 14.6638
4 x KAIDEPYLVÄS | +2.260 | +4.510 | 24.3 | 53.3 | 1.3 | 2250 | 2250 | 1.296 | 0.0405 | 24.3
4 x KAIDEPYLVÄS | +2.283 | +4.533 | 24.3 | 53.3 | 1.3 | 2250 | 2250 | 1.296 | 0.0405 | 24.3
4 x KAIDEPYLVÄS | +2.300 | +4.550 | 24.3 | 53.3 | 1.3 | 2250 | 2250 | 1.296 | 0.0405 | 24.3
4 x KAIDEPYLVÄS | +2.310 | +4.560 | 24.3 | 53.3 | 1.3 | 2250 | 2250 | 1.296 | 0.0405 | 24.3
2 x KAIDEPYLVÄS | +2.313 | +4.563 | 24.3 | 53.3 | 1.3 | 2250 | 2250 | 1.296 | 0.0405 | 24.3

# IfcColumn: 524*639 (4)
In: Undefined
Description: 524*639; Material: CONCRETE/Concrete_Undefined
Pset_ColumnCommon - LoadBearing: yes; Reference: Concrete_P-1/0(?)
Tekla Common - Bottom elevation: +1.912; Top elevation: +1.975; Phase: 600; Class: 320
Tekla Quantity - Weight: 36.8 kg; Volume: 0 m3; Gross footprint area: 0.2 m2; Area per tons: 19 m2; Net surface area: 0.6 m2; Height: 514.8 mm; Width: 639 mm; Length: 63.5 mm
BaseQuantities - Length: 63.5137 mm; OuterSurfaceArea: 0.69991 m2; NetVolume: 0.0153352 m3; NetWeight: 36.8044 kg

# IfcColumn: 570*685 (4)
In: Undefined
Description: 570*685; Material: CONCRETE/Concrete_Undefined
Pset_ColumnCommon - LoadBearing: yes; Reference: Concrete_P-1/0(?)
Tekla Common - Bottom elevation: +1.911; Top elevation: +1.997; Phase: 600; Class: 320
Tekla Quantity - Weight: 55.5 kg; Volume: 0 m3; Gross footprint area: 0.2 m2; Area per tons: 14.9 m2; Net surface area: 0.8 m2; Height: 559.7 mm; Width: 685 mm; Length: 86 mm
BaseQuantities - Length: 85.9822 mm; OuterSurfaceArea: 0.828549 m2; NetVolume: 0.0231346 m3; NetWeight: 55.523 kg

# IfcColumn: 70*45 (288)
In: Undefined
Description: 70*45; Material: TIMBER/Timber_Undefined
Tekla Common - Phase: 600; Class: 1
Tekla Quantity - Volume: 0 m3; Gross footprint area: 0 m2; Height: 70 mm; Width: 45 mm
Pset_ColumnCommon - LoadBearing: yes; Reference: P/0(?)
Name | Bottom elevation | Top elevation | Weight (kg) | Area per tons (m2) | Net surface area (m2) | Tekla Quantity, Length (mm) | BaseQuantities, Length (mm) | OuterSurfaceArea (m2) | NetVolume (m3) | NetWeight (kg)
4 x BEAM | +3.148 | +4.455 | 2.5 | 124.3 | 0.3 | 1307.2 | 1307.2 | 0.305469 | 0.00409542 | 2.45725
4 x BEAM | +3.146 | +4.409 | 2.5 | 124.3 | 0.3 | 1263.3 | 1263.28 | 0.295369 | 0.0039571 | 2.37426
4 x BEAM | +3.143 | +4.363 | 2.3 | 124.5 | 0.3 | 1219.4 | 1219.37 | 0.285269 | 0.00381878 | 2.29127
4 x BEAM | +3.141 | +4.316 | 2.2 | 124.6 | 0.3 | 1175.5 | 1175.46 | 0.27517 | 0.00368046 | 2.20828
4 x BEAM | +3.138 | +4.270 | 2.1 | 124.6 | 0.3 | 1131.5 | 1131.55 | 0.26507 | 0.00354214 | 2.12528
4 x BEAM | +3.136 | +4.224 | 2 | 124.8 | 0.3 | 1087.6 | 1087.64 | 0.25497 | 0.00340382 | 2.04229
4 x BEAM | +3.134 | +4.177 | 2 | 125 | 0.2 | 1043.7 | 1043.73 | 0.244871 | 0.0032655 | 1.9593
4 x BEAM | +3.131 | +4.131 | 2 | 125.1 | 0.2 | 999.8 | 999.815 | 0.234771 | 0.00312717 | 1.8763
4 x BEAM | +3.129 | +4.085 | 1.8 | 125.3 | 0.2 | 955.9 | 955.904 | 0.224671 | 0.00298885 | 1.79331
4 x BEAM | +3.127 | +4.039 | 1.8 | 125.5 | 0.2 | 912 | 911.992 | 0.214572 | 0.00285053 | 1.71032
4 x BEAM | +3.124 | +3.992 | 1.6 | 125.6 | 0.2 | 868.1 | 868.08 | 0.204472 | 0.00271221 | 1.62733
4 x BEAM | +3.122 | +3.946 | 1.5 | 125.9 | 0.2 | 824.2 | 824.169 | 0.194373 | 0.00257389 | 1.54433
4 x BEAM | +3.178 | +4.509 | 2.5 | 124.2 | 0.3 | 1330.7 | 1330.69 | 0.312201 | 0.0041895 | 2.5137
4 x BEAM | +3.176 | +4.507 | 2.5 | 124.2 | 0.3 | 1330.7 | 1330.69 | 0.312201 | 0.0041895 | 2.5137
4 x BEAM | +3.174 | +4.504 | 2.5 | 124.2 | 0.3 | 1330.7 | 1330.69 | 0.312201 | 0.0041895 | 2.5137
4 x BEAM | +3.171 | +4.502 | 2.5 | 124.2 | 0.3 | 1330.7 | 1330.69 | 0.312201 | 0.0041895 | 2.5137
4 x BEAM | +3.169 | +4.500 | 2.5 | 124.2 | 0.3 | 1330.7 | 1330.69 | 0.312201 | 0.0041895 | 2.5137
4 x BEAM | +3.167 | +4.497 | 2.5 | 124.2 | 0.3 | 1330.7 | 1330.69 | 0.312201 | 0.0041895 | 2.5137
4 x BEAM | +3.164 | +4.495 | 2.5 | 124.2 | 0.3 | 1330.7 | 1330.69 | 0.312201 | 0.0041895 | 2.5137
4 x BEAM | +3.162 | +4.493 | 2.5 | 124.2 | 0.3 | 1330.7 | 1330.69 | 0.312201 | 0.0041895 | 2.5137
4 x BEAM | +3.160 | +4.490 | 2.5 | 124.2 | 0.3 | 1330.7 | 1330.69 | 0.312201 | 0.0041895 | 2.5137
4 x BEAM | +3.157 | +4.488 | 2.5 | 124.2 | 0.3 | 1330.7 | 1330.69 | 0.312201 | 0.0041895 | 2.5137
4 x BEAM | +3.155 | +4.485 | 2.5 | 124.2 | 0.3 | 1330.7 | 1330.69 | 0.312201 | 0.0041895 | 2.5137
4 x BEAM | +3.152 | +4.483 | 2.5 | 124.2 | 0.3 | 1330.7 | 1330.69 | 0.312201 | 0.0041895 | 2.5137
2 x BEAM | +2.881 | +4.512 | 3.1 | 123.7 | 0.3 | 1630.6 | 1630.55 | 0.381202 | 0.00513452 | 3.08071
2 x BEAM | +2.883 | +4.514 | 3.1 | 123.7 | 0.3 | 1630.6 | 1630.55 | 0.381202 | 0.00513452 | 3.08071
2 x BEAM | +2.885 | +4.516 | 3.1 | 123.7 | 0.3 | 1630.6 | 1630.55 | 0.381202 | 0.00513452 | 3.08071
2 x BEAM | +2.887 | +4.517 | 3.1 | 123.7 | 0.3 | 1630.6 | 1630.55 | 0.381202 | 0.00513452 | 3.08071
2 x BEAM | +2.889 | +4.519 | 3.1 | 123.7 | 0.3 | 1630.6 | 1630.55 | 0.381202 | 0.00513452 | 3.08071
2 x BEAM | +2.891 | +4.521 | 3.1 | 123.7 | 0.3 | 1630.6 | 1630.55 | 0.381202 | 0.00513452 | 3.08071
2 x BEAM | +2.893 | +4.523 | 3.1 | 123.7 | 0.3 | 1630.6 | 1630.55 | 0.381202 | 0.00513452 | 3.08071
2 x BEAM | +2.894 | +4.525 | 3.1 | 123.7 | 0.3 | 1630.6 | 1630.55 | 0.381202 | 0.00513452 | 3.08071
2 x BEAM | +2.896 | +4.527 | 3.1 | 123.7 | 0.3 | 1630.6 | 1630.55 | 0.381202 | 0.00513452 | 3.08071
2 x BEAM | +2.898 | +4.529 | 3.1 | 123.7 | 0.3 | 1630.6 | 1630.55 | 0.381202 | 0.00513452 | 3.08071
2 x BEAM | +2.900 | +4.531 | 3.1 | 123.7 | 0.3 | 1630.6 | 1630.55 | 0.381202 | 0.00513452 | 3.08071
2 x BEAM | +2.902 | +4.533 | 3.1 | 123.7 | 0.3 | 1630.6 | 1630.55 | 0.381202 | 0.00513452 | 3.08071
2 x BEAM | +2.904 | +4.535 | 3.1 | 123.7 | 0.3 | 1630.4 | 1630.4 | 0.381201 | 0.00513451 | 3.08071
2 x BEAM | +2.905 | +4.536 | 3.1 | 123.7 | 0.3 | 1630.4 | 1630.4 | 0.381201 | 0.00513451 | 3.08071
2 x BEAM | +2.907 | +4.537 | 3.1 | 123.7 | 0.3 | 1630.4 | 1630.4 | 0.381201 | 0.00513451 | 3.08071
2 x BEAM | +2.908 | +4.539 | 3.1 | 123.7 | 0.3 | 1630.4 | 1630.4 | 0.381201 | 0.00513451 | 3.08071
2 x BEAM | +2.910 | +4.540 | 3.1 | 123.7 | 0.3 | 1630.4 | 1630.4 | 0.381201 | 0.00513451 | 3.08071
2 x BEAM | +2.911 | +4.541 | 3.1 | 123.7 | 0.3 | 1630.4 | 1630.4 | 0.381201 | 0.00513451 | 3.08071
2 x BEAM | +2.912 | +4.543 | 3.1 | 123.7 | 0.3 | 1630.4 | 1630.4 | 0.381201 | 0.00513451 | 3.08071
2 x BEAM | +2.914 | +4.544 | 3.1 | 123.7 | 0.3 | 1630.4 | 1630.4 | 0.381201 | 0.00513451 | 3.08071
2 x BEAM | +2.915 | +4.545 | 3.1 | 123.7 | 0.3 | 1630.4 | 1630.4 | 0.381201 | 0.00513451 | 3.08071
2 x BEAM | +2.916 | +4.547 | 3.1 | 123.7 | 0.3 | 1630.4 | 1630.4 | 0.381201 | 0.00513451 | 3.08071
2 x BEAM | +2.918 | +4.548 | 3.1 | 123.7 | 0.3 | 1630.4 | 1630.4 | 0.381201 | 0.00513451 | 3.08071
2 x BEAM | +2.919 | +4.549 | 3.1 | 123.7 | 0.3 | 1630.4 | 1630.4 | 0.381201 | 0.00513451 | 3.08071
2 x BEAM | +2.920 | +4.551 | 3.1 | 123.7 | 0.3 | 1630.2 | 1630.24 | 0.3812 | 0.0051345 | 3.0807
4 x BEAM | +2.921 | +4.551 | 3.1 | 123.7 | 0.3 | 1630.2 | 1630.24 | 0.3812 | 0.0051345 | 3.0807
4 x BEAM | +2.922 | +4.552 | 3.1 | 123.7 | 0.3 | 1630.2 | 1630.24 | 0.3812 | 0.0051345 | 3.0807
4 x BEAM | +2.923 | +4.553 | 3.1 | 123.7 | 0.3 | 1630.2 | 1630.24 | 0.3812 | 0.0051345 | 3.0807
4 x BEAM | +2.924 | +4.554 | 3.1 | 123.7 | 0.3 | 1630.2 | 1630.24 | 0.3812 | 0.0051345 | 3.0807
2 x BEAM | +2.924 | +4.555 | 3.1 | 123.7 | 0.3 | 1630.2 | 1630.24 | 0.3812 | 0.0051345 | 3.0807
2 x BEAM | +2.925 | +4.556 | 3.1 | 123.7 | 0.3 | 1630.2 | 1630.24 | 0.3812 | 0.0051345 | 3.0807
4 x BEAM | +2.926 | +4.556 | 3.1 | 123.7 | 0.3 | 1630.2 | 1630.24 | 0.3812 | 0.0051345 | 3.0807
4 x BEAM | +2.927 | +4.557 | 3.1 | 123.7 | 0.3 | 1630.2 | 1630.24 | 0.3812 | 0.0051345 | 3.0807
2 x BEAM | +2.928 | +4.558 | 3.1 | 123.7 | 0.3 | 1630.2 | 1630.24 | 0.3812 | 0.0051345 | 3.0807
2 x BEAM | +2.929 | +4.559 | 3.1 | 123.7 | 0.3 | 1630.2 | 1630.24 | 0.3812 | 0.0051345 | 3.0807
2 x BEAM | +2.929 | +4.560 | 3.1 | 123.7 | 0.3 | 1630.2 | 1630.24 | 0.3812 | 0.0051345 | 3.0807
8 x BEAM | +2.930 | +4.560 | 3.1 | 123.7 | 0.3 | 1630.2 | 1630.08 | 0.3812 | 0.0051345 | 3.0807
12 x BEAM | +2.931 | +4.561 | 3.1 | 123.7 | 0.3 | 1630.2 | 1630.08 | 0.3812 | 0.0051345 | 3.0807
4 x BEAM | +2.931 | +4.562 | 3.1 | 123.7 | 0.3 | 1630.2 | 1630.08 | 0.3812 | 0.0051345 | 3.0807
12 x BEAM | +2.932 | +4.562 | 3.1 | 123.7 | 0.3 | 1630.2 | 1630.08 | 0.3812 | 0.0051345 | 3.0807
12 x BEAM | +2.933 | +4.563 | 3.1 | 123.7 | 0.3 | 1630.2 | 1630.08 | 0.3812 | 0.0051345 | 3.0807
2 x BEAM | +2.925 | +4.555 | 3.1 | 123.7 | 0.3 | 1630.2 | 1630.24 | 0.3812 | 0.0051345 | 3.0807
2 x BEAM | +2.923 | +4.554 | 3.1 | 123.7 | 0.3 | 1630.2 | 1630.24 | 0.3812 | 0.0051345 | 3.0807
2 x BEAM | +2.920 | +4.550 | 3.1 | 123.7 | 0.3 | 1630.2 | 1630.24 | 0.3812 | 0.0051345 | 3.0807
2 x BEAM | +2.919 | +4.550 | 3.1 | 123.7 | 0.3 | 1630.2 | 1630.24 | 0.3812 | 0.0051345 | 3.0807
2 x BEAM | +2.919 | +4.549 | 3.1 | 123.7 | 0.3 | 1630.2 | 1630.24 | 0.3812 | 0.0051345 | 3.0807
2 x BEAM | +2.918 | +4.548 | 3.1 | 123.7 | 0.3 | 1630.2 | 1630.24 | 0.3812 | 0.0051345 | 3.0807
2 x BEAM | +2.919 | +4.549 | 3.1 | 123.7 | 0.3 | 1630.4 | 1630.39 | 0.381199 | 0.00513448 | 3.08069
2 x BEAM | +2.918 | +4.548 | 3.1 | 123.7 | 0.3 | 1630.4 | 1630.39 | 0.381199 | 0.00513448 | 3.08069
2 x BEAM | +2.916 | +4.547 | 3.1 | 123.7 | 0.3 | 1630.4 | 1630.39 | 0.381199 | 0.00513448 | 3.08069
2 x BEAM | +2.915 | +4.545 | 3.1 | 123.7 | 0.3 | 1630.4 | 1630.39 | 0.381199 | 0.00513448 | 3.08069
2 x BEAM | +2.914 | +4.544 | 3.1 | 123.7 | 0.3 | 1630.4 | 1630.39 | 0.381199 | 0.00513448 | 3.08069
2 x BEAM | +2.912 | +4.543 | 3.1 | 123.7 | 0.3 | 1630.4 | 1630.39 | 0.381199 | 0.00513448 | 3.08069
2 x BEAM | +2.911 | +4.541 | 3.1 | 123.7 | 0.3 | 1630.4 | 1630.39 | 0.381199 | 0.00513448 | 3.08069
2 x BEAM | +2.910 | +4.540 | 3.1 | 123.7 | 0.3 | 1630.4 | 1630.39 | 0.381199 | 0.00513448 | 3.08069
2 x BEAM | +2.908 | +4.539 | 3.1 | 123.7 | 0.3 | 1630.4 | 1630.39 | 0.381199 | 0.00513448 | 3.08069
2 x BEAM | +2.907 | +4.537 | 3.1 | 123.7 | 0.3 | 1630.4 | 1630.39 | 0.381199 | 0.00513448 | 3.08069
2 x BEAM | +2.905 | +4.536 | 3.1 | 123.7 | 0.3 | 1630.4 | 1630.39 | 0.381199 | 0.00513448 | 3.08069
2 x BEAM | +2.904 | +4.535 | 3.1 | 123.7 | 0.3 | 1630.4 | 1630.39 | 0.381199 | 0.00513448 | 3.08069
2 x BEAM | +2.902 | +4.533 | 3.1 | 123.7 | 0.3 | 1630.4 | 1630.55 | 0.3812 | 0.00513449 | 3.08069
2 x BEAM | +2.900 | +4.531 | 3.1 | 123.7 | 0.3 | 1630.4 | 1630.55 | 0.3812 | 0.00513449 | 3.08069
2 x BEAM | +2.898 | +4.529 | 3.1 | 123.7 | 0.3 | 1630.4 | 1630.55 | 0.3812 | 0.00513449 | 3.08069
2 x BEAM | +2.896 | +4.527 | 3.1 | 123.7 | 0.3 | 1630.4 | 1630.55 | 0.3812 | 0.00513449 | 3.08069
2 x BEAM | +2.894 | +4.525 | 3.1 | 123.7 | 0.3 | 1630.4 | 1630.55 | 0.3812 | 0.00513449 | 3.08069
2 x BEAM | +2.893 | +4.523 | 3.1 | 123.7 | 0.3 | 1630.4 | 1630.55 | 0.3812 | 0.00513449 | 3.08069
2 x BEAM | +2.891 | +4.521 | 3.1 | 123.7 | 0.3 | 1630.4 | 1630.55 | 0.3812 | 0.00513449 | 3.08069
2 x BEAM | +2.889 | +4.519 | 3.1 | 123.7 | 0.3 | 1630.4 | 1630.55 | 0.3812 | 0.00513449 | 3.08069
2 x BEAM | +2.887 | +4.517 | 3.1 | 123.7 | 0.3 | 1630.4 | 1630.55 | 0.3812 | 0.00513449 | 3.08069
2 x BEAM | +2.885 | +4.516 | 3.1 | 123.7 | 0.3 | 1630.4 | 1630.55 | 0.3812 | 0.00513449 | 3.08069
2 x BEAM | +2.883 | +4.514 | 3.1 | 123.7 | 0.3 | 1630.4 | 1630.55 | 0.3812 | 0.00513449 | 3.08069
2 x BEAM | +2.881 | +4.512 | 3.1 | 123.7 | 0.3 | 1630.4 | 1630.55 | 0.3812 | 0.00513449 | 3.08069

# IfcColumn: D33 (16)
In: Undefined
Description: D33; Material: STEEL/Steel_Undefined
Pset_ColumnCommon - LoadBearing: yes; Reference: P/0(?)
Tekla Common - Phase: 600; Class: 1
Tekla Quantity - Weight: 0.1 kg; Volume: 0 m3; Gross footprint area: 0 m2; Area per tons: 30.1 m2; Net surface area: 0 m2; Height: 33 mm; Width: 33 mm; Length: 18 mm
BaseQuantities - Length: 18 mm; OuterSurfaceArea: 0.00347836 m2; NetVolume: 0.0000147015 m3; NetWeight: 0.115407 kg
Name | Bottom elevation | Top elevation
8 x BEAM | +2.015 | +2.033
8 x BEAM | +1.993 | +2.011

# IfcColumn: D38 (16)
In: Undefined
Description: D38; Material: STEEL/Steel_Undefined
Pset_ColumnCommon - LoadBearing: yes; Reference: P/0(?)
Tekla Common - Phase: 600; Class: 1
Tekla Quantity - Weight: 0.1 kg; Volume: 0 m3; Gross footprint area: 0 m2; Area per tons: 45.7 m2; Net surface area: 0 m2; Height: 38 mm; Width: 38 mm; Length: 8 mm
BaseQuantities - Length: 8 mm; OuterSurfaceArea: 0.00311017 m2; NetVolume: 0.000008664 m3; NetWeight: 0.0680124 kg
Name | Bottom elevation | Top elevation
8 x BEAM | +2.007 | +2.015
8 x BEAM | +1.985 | +1.993

# IfcColumn: D400 (4)
In: Undefined
Description: D400; Material: CONCRETE/Concrete_Undefined
Tekla Common - Bottom elevation: +2.445; Top elevation: +3.045; Phase: 600; Class: 320
Tekla Quantity - Weight: 180 kg; Volume: 0.1 m3; Gross footprint area: 0.1 m2; Area per tons: 5.6 m2; Net surface area: 1 m2; Height: 400 mm; Width: 400 mm; Length: 600 mm
Pset_ColumnCommon - LoadBearing: yes; Reference: Concrete_P-1/0(?)
BaseQuantities - Length: 600 mm; OuterSurfaceArea: 1.00308 m2; NetVolume: 0.075016 m3; NetWeight: 180.038 kg

# IfcColumn: PL150*10 (16)
In: Undefined
Description: PL150*10; Material: STEEL/AISI316
Tekla Common - Phase: 600; Class: 8013
Tekla Quantity - Weight: 6.8 kg; Volume: 0 m3; Gross footprint area: 0 m2; Area per tons: 27.7 m2; Net surface area: 0.2 m2; Height: 150 mm; Width: 10 mm; Length: 620 mm
Pset_ColumnCommon - LoadBearing: yes; Reference: KPL/0(?)
BaseQuantities - Length: 620 mm; OuterSurfaceArea: 0.1889 m2; NetVolume: 0.0008675 m3; NetWeight: 6.80988 kg
Name | Bottom elevation | Top elevation
8 x KAIDEPYLVÄS | +2.795 | +3.415
8 x KAIDEPYLVÄS | +2.823 | +3.443

# IfcColumn: PL300*215 (8)
In: Undefined
Description: PL300*215; Material: MISCELLANEOUS/NEOPREENI
Pset_ColumnCommon - LoadBearing: yes; Reference: P/0(?)
Tekla Common - Phase: 600; Class: 7
Tekla Quantity - Weight: 0.9 kg; Volume: 0 m3; Gross footprint area: 0.1 m2; Area per tons: 154.3 m2; Net surface area: 0.1 m2; Height: 300 mm; Width: 215 mm; Length: 10 mm
BaseQuantities - Length: 10 mm; OuterSurfaceArea: 0.1393 m2; NetVolume: 0.000645 m3; NetWeight: 0.903 kg
Name | Bottom elevation | Top elevation
4 x COLUMN | +1.975 | +1.985
4 x COLUMN | +1.997 | +2.007

# IfcCovering (20)
In: Undefined
Material: Undefined/Undefined
Tekla Surface Treatment - Content Type: SURFACE; Name: MUOTTI; Type: Formwork
Name | Area (m2)
2 x SurfaceObject | 1.6
2 x SurfaceObject | 7.2
2 x SurfaceObject | 4.5
4 x SurfaceObject | 0.1
3 x SurfaceObject | 4.6
2 x SurfaceObject | 0.2
SurfaceObject | 3.8
2 x SurfaceObject | 1
2 x SurfaceObject | 2.1

# IfcMechanicalFastener: Bolt assembly (24)
In: Undefined
NominalDiameter: 20 mm; Material: Undefined
Tekla Bolt - Washer diameter: 20 mm; Washer type: DIN125; Washer name: W20-DIN125; Nut type: DIN934; Nut name: M20-DIN934; Slotted hole y: 0 mm; Location: Site
Name | NominalLength (mm) = Bolt length (mm) | Washer count | Nut count | Slotted hole x (mm) | Bolt hole diameter (mm) | Bolt count | Bolt size (mm) | Bolt standard | Bolt Name
16 x Bolt assembly | 30 | 0 | 0 | 30 | 30 | 1 | 30 | DIN933 | M20*30
8 x Bolt assembly | 270 | 4 | 2 | 0 | 22 | 2 | 20 | DIN931 | M20*270

# IfcReinforcingBar (16)
In: Undefined
NominalDiameter: 23 mm; CrossSectionArea: 0 m2; Material: A500HW
Tekla Reinforcement - TD: 40 mm; r: 20 mm; c: 311 mm; b: 378 mm; a: 311 mm; Length: 920 mm; Total Weight: 2.3 kg; Weight: 2.3 kg; Cast unit mark: LP/0(?); Phase: 100; Total Number: 1; Grade: A500HW; Name: REBAR; Size: 20; Rebar Mark: 0(?); Shape: D

# IfcSlab: 400*2500 (2)
In: Undefined
Description: 400*2500; PredefinedType: FLOOR; Material: CONCRETE/Concrete_Undefined
Tekla Common - Bottom elevation: +0.000; Top elevation: +0.400; Phase: 100; Class: 1003
Tekla Quantity - Weight: 12312 kg; Volume: 5.1 m3; Gross footprint area: 12.8 m2; Area per tons: 2.6 m2; Net surface area: 31.8 m2; Height: 2500 mm; Width: 400 mm; Length: 5130 mm
Pset_SlabCommon - LoadBearing: yes; Reference: Concrete_PL-1/0(?)
BaseQuantities - Width: 400 mm; NetVolume: 5.13 m3; NetArea: 12.825 m2; NetWeight: 12312 kg
